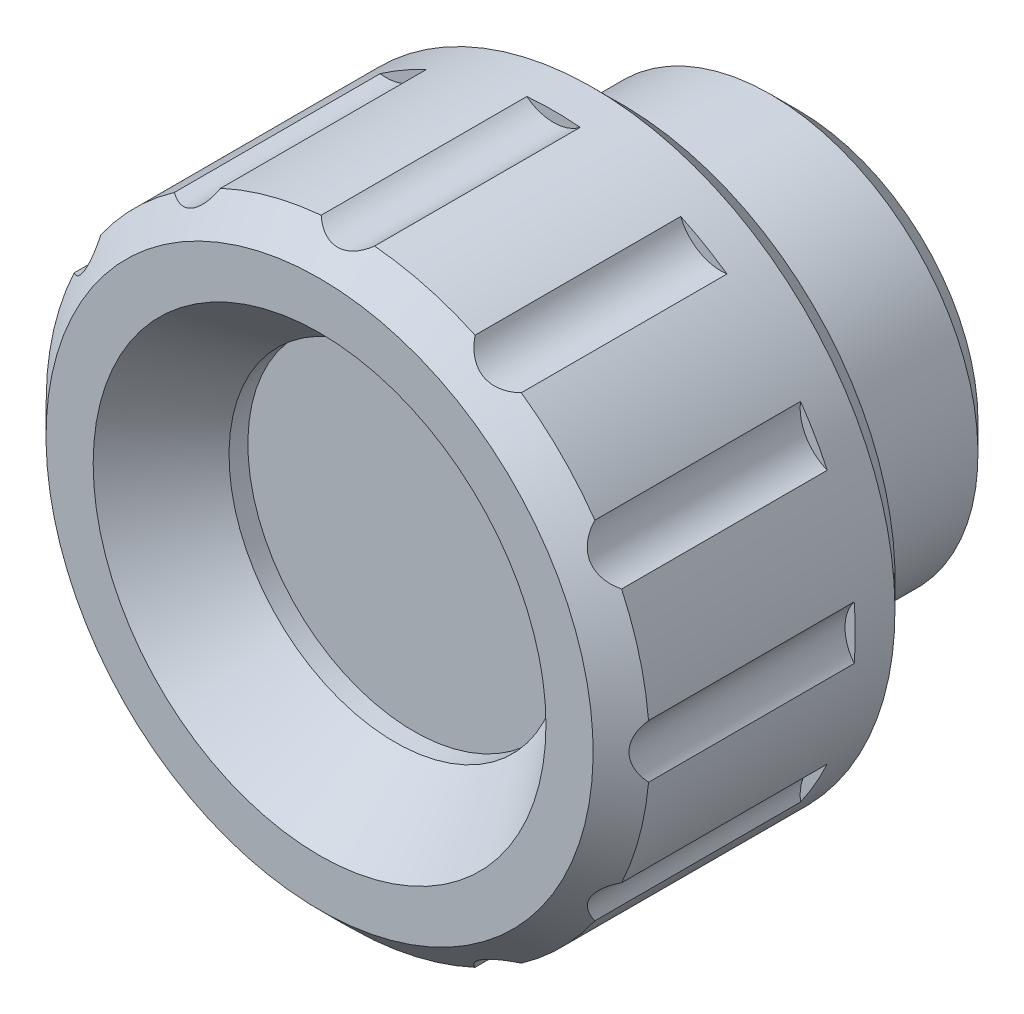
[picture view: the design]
ISO-10303-21;
HEADER;
FILE_DESCRIPTION(('STEP AP214'),'2;1');
FILE_NAME('part.step','',(''),(''),'','','');
FILE_SCHEMA(('AUTOMOTIVE_DESIGN { 1 0 10303 214 1 1 1 1 }'));
ENDSEC;
DATA;
#1=APPLICATION_CONTEXT('core data for automotive mechanical design processes');
#2=APPLICATION_PROTOCOL_DEFINITION('international standard','automotive_design',2000,#1);
#3=PRODUCT_CONTEXT('',#1,'mechanical');
#4=PRODUCT('Part','Part','',(#3));
#5=PRODUCT_RELATED_PRODUCT_CATEGORY('part','',(#4));
#6=PRODUCT_DEFINITION_FORMATION('','',#4);
#7=PRODUCT_DEFINITION_CONTEXT('part definition',#1,'design');
#8=PRODUCT_DEFINITION('design','',#6,#7);
#9=PRODUCT_DEFINITION_SHAPE('','',#8);
#10=(LENGTH_UNIT() NAMED_UNIT(*) SI_UNIT(.MILLI.,.METRE.));
#11=(NAMED_UNIT(*) PLANE_ANGLE_UNIT() SI_UNIT($,.RADIAN.));
#12=(NAMED_UNIT(*) SI_UNIT($,.STERADIAN.) SOLID_ANGLE_UNIT());
#13=UNCERTAINTY_MEASURE_WITH_UNIT(LENGTH_MEASURE(1.E-05),#10,'distance_accuracy_value','');
#14=(GEOMETRIC_REPRESENTATION_CONTEXT(3) GLOBAL_UNCERTAINTY_ASSIGNED_CONTEXT((#13)) GLOBAL_UNIT_ASSIGNED_CONTEXT((#10,
#11,#12)) REPRESENTATION_CONTEXT('',''));
#15=CARTESIAN_POINT('',(0.,0.,0.));
#16=DIRECTION('',(0.,0.,1.));
#17=DIRECTION('',(1.,0.,0.));
#18=AXIS2_PLACEMENT_3D('',#15,#16,#17);
#19=CARTESIAN_POINT('',(3.49999999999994,0.,0.));
#20=DIRECTION('',(0.,0.,-1.));
#21=DIRECTION('',(0.,1.,0.));
#22=AXIS2_PLACEMENT_3D('',#19,#20,#21);
#23=PLANE('',#22);
#24=CARTESIAN_POINT('',(0.,0.,0.));
#25=DIRECTION('',(0.,0.,-1.));
#26=DIRECTION('',(-1.,0.,0.));
#27=AXIS2_PLACEMENT_3D('',#24,#25,#26);
#28=CIRCLE('',#27,2.4);
#29=CARTESIAN_POINT('',(-2.4,0.,0.));
#30=VERTEX_POINT('',#29);
#31=EDGE_CURVE('E9',#30,#30,#28,.F.);
#32=ORIENTED_EDGE('',*,*,#31,.T.);
#33=EDGE_LOOP('',(#32));
#34=FACE_BOUND('',#33,.T.);
#35=CARTESIAN_POINT('',(0.,0.,0.));
#36=DIRECTION('',(0.,0.,-1.));
#37=DIRECTION('',(0.,1.,0.));
#38=AXIS2_PLACEMENT_3D('',#35,#36,#37);
#39=CIRCLE('',#38,3.49999999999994);
#40=CARTESIAN_POINT('',(0.,3.49999999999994,0.));
#41=VERTEX_POINT('',#40);
#42=EDGE_CURVE('E354',#41,#41,#39,.T.);
#43=ORIENTED_EDGE('',*,*,#42,.T.);
#44=EDGE_LOOP('',(#43));
#45=FACE_BOUND('',#44,.T.);
#46=ADVANCED_FACE('F14',(#34,#45),#23,.T.);
#47=CARTESIAN_POINT('',(0.,0.,0.));
#48=DIRECTION('',(0.,0.,-1.));
#49=DIRECTION('',(0.,1.,0.));
#50=AXIS2_PLACEMENT_3D('',#47,#48,#49);
#51=CYLINDRICAL_SURFACE('',#50,3.49999999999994);
#52=CARTESIAN_POINT('',(0.,0.,0.300000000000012));
#53=DIRECTION('',(0.,0.,-1.));
#54=DIRECTION('',(0.,1.,0.));
#55=AXIS2_PLACEMENT_3D('',#52,#53,#54);
#56=CIRCLE('',#55,3.49999999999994);
#57=CARTESIAN_POINT('',(0.,3.49999999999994,0.300000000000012));
#58=VERTEX_POINT('',#57);
#59=EDGE_CURVE('E351',#58,#58,#56,.T.);
#60=ORIENTED_EDGE('',*,*,#59,.T.);
#61=EDGE_LOOP('',(#60));
#62=FACE_BOUND('',#61,.T.);
#63=ORIENTED_EDGE('',*,*,#42,.F.);
#64=EDGE_LOOP('',(#63));
#65=FACE_BOUND('',#64,.T.);
#66=ADVANCED_FACE('F406',(#62,#65),#51,.T.);
#67=CARTESIAN_POINT('',(4.74999999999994,0.,0.300000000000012));
#68=DIRECTION('',(0.,0.,-1.));
#69=DIRECTION('',(0.,1.,0.));
#70=AXIS2_PLACEMENT_3D('',#67,#68,#69);
#71=PLANE('',#70);
#72=CARTESIAN_POINT('',(0.,0.,0.300000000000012));
#73=DIRECTION('',(0.,0.,-1.));
#74=DIRECTION('',(0.,1.,0.));
#75=AXIS2_PLACEMENT_3D('',#72,#73,#74);
#76=CIRCLE('',#75,4.74999999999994);
#77=CARTESIAN_POINT('',(0.,4.74999999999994,0.300000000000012));
#78=VERTEX_POINT('',#77);
#79=EDGE_CURVE('E348',#78,#78,#76,.T.);
#80=ORIENTED_EDGE('',*,*,#79,.T.);
#81=EDGE_LOOP('',(#80));
#82=FACE_BOUND('',#81,.T.);
#83=ORIENTED_EDGE('',*,*,#59,.F.);
#84=EDGE_LOOP('',(#83));
#85=FACE_BOUND('',#84,.T.);
#86=ADVANCED_FACE('F413',(#82,#85),#71,.T.);
#87=CARTESIAN_POINT('',(0.,0.,0.300000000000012));
#88=DIRECTION('',(0.,0.,1.));
#89=DIRECTION('',(0.,-1.,0.));
#90=AXIS2_PLACEMENT_3D('',#87,#88,#89);
#91=CONICAL_SURFACE('',#90,4.74999999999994,0.785398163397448);
#92=CARTESIAN_POINT('',(0.,0.,1.05000000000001));
#93=DIRECTION('',(0.,0.,-1.));
#94=DIRECTION('',(0.,1.,0.));
#95=AXIS2_PLACEMENT_3D('',#92,#93,#94);
#96=CIRCLE('',#95,5.49999999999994);
#97=CARTESIAN_POINT('',(0.,5.49999999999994,1.05000000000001));
#98=VERTEX_POINT('',#97);
#99=EDGE_CURVE('E344',#98,#98,#96,.T.);
#100=ORIENTED_EDGE('',*,*,#99,.T.);
#101=EDGE_LOOP('',(#100));
#102=FACE_BOUND('',#101,.T.);
#103=ORIENTED_EDGE('',*,*,#79,.F.);
#104=EDGE_LOOP('',(#103));
#105=FACE_BOUND('',#104,.T.);
#106=ADVANCED_FACE('F864',(#102,#105),#91,.T.);
#107=CARTESIAN_POINT('',(0.,0.,0.));
#108=DIRECTION('',(0.,0.,-1.));
#109=DIRECTION('',(0.,1.,0.));
#110=AXIS2_PLACEMENT_3D('',#107,#108,#109);
#111=CYLINDRICAL_SURFACE('',#110,5.49999999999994);
#112=CARTESIAN_POINT('',(0.,0.,5.));
#113=DIRECTION('',(0.,0.,-1.));
#114=DIRECTION('',(-1.,0.,0.));
#115=AXIS2_PLACEMENT_3D('',#112,#113,#114);
#116=CIRCLE('',#115,5.49999999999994);
#117=CARTESIAN_POINT('',(-5.49999999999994,0.,5.));
#118=VERTEX_POINT('',#117);
#119=EDGE_CURVE('E211',#118,#118,#116,.F.);
#120=ORIENTED_EDGE('',*,*,#119,.F.);
#121=EDGE_LOOP('',(#120));
#122=FACE_BOUND('',#121,.T.);
#123=ORIENTED_EDGE('',*,*,#99,.F.);
#124=EDGE_LOOP('',(#123));
#125=FACE_BOUND('',#124,.T.);
#126=ADVANCED_FACE('F465',(#122,#125),#111,.T.);
#127=CARTESIAN_POINT('',(0.,8.,5.));
#128=DIRECTION('',(0.,0.,-1.));
#129=DIRECTION('',(-1.,0.,0.));
#130=AXIS2_PLACEMENT_3D('',#127,#128,#129);
#131=PLANE('',#130);
#132=CARTESIAN_POINT('',(0.,0.,5.));
#133=DIRECTION('',(0.,0.,-1.));
#134=DIRECTION('',(-1.,0.,0.));
#135=AXIS2_PLACEMENT_3D('',#132,#133,#134);
#136=CIRCLE('',#135,7.25);
#137=CARTESIAN_POINT('',(-7.25,0.,5.));
#138=VERTEX_POINT('',#137);
#139=EDGE_CURVE('E216',#138,#138,#136,.T.);
#140=ORIENTED_EDGE('',*,*,#139,.T.);
#141=EDGE_LOOP('',(#140));
#142=FACE_BOUND('',#141,.T.);
#143=ORIENTED_EDGE('',*,*,#119,.T.);
#144=EDGE_LOOP('',(#143));
#145=FACE_BOUND('',#144,.T.);
#146=ADVANCED_FACE('F420',(#142,#145),#131,.T.);
#147=CARTESIAN_POINT('',(4.4,0.,10.5000000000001));
#148=DIRECTION('',(0.,0.,1.));
#149=DIRECTION('',(0.,-1.,0.));
#150=AXIS2_PLACEMENT_3D('',#147,#148,#149);
#151=PLANE('',#150);
#152=CARTESIAN_POINT('',(0.,0.,10.5000000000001));
#153=DIRECTION('',(0.,0.,-1.));
#154=DIRECTION('',(0.,1.,0.));
#155=AXIS2_PLACEMENT_3D('',#152,#153,#154);
#156=CIRCLE('',#155,4.4);
#157=CARTESIAN_POINT('',(0.,4.4,10.5000000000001));
#158=VERTEX_POINT('',#157);
#159=EDGE_CURVE('E288',#158,#158,#156,.T.);
#160=ORIENTED_EDGE('',*,*,#159,.F.);
#161=EDGE_LOOP('',(#160));
#162=FACE_BOUND('',#161,.T.);
#163=ADVANCED_FACE('F394',(#162),#151,.T.);
#164=CARTESIAN_POINT('',(0.,0.,0.));
#165=DIRECTION('',(0.,0.,-1.));
#166=DIRECTION('',(0.,1.,0.));
#167=AXIS2_PLACEMENT_3D('',#164,#165,#166);
#168=CYLINDRICAL_SURFACE('',#167,4.4);
#169=ORIENTED_EDGE('',*,*,#159,.T.);
#170=EDGE_LOOP('',(#169));
#171=FACE_BOUND('',#170,.T.);
#172=CARTESIAN_POINT('',(0.,0.,11.));
#173=DIRECTION('',(0.,0.,-1.));
#174=DIRECTION('',(0.,1.,0.));
#175=AXIS2_PLACEMENT_3D('',#172,#173,#174);
#176=CIRCLE('',#175,4.4);
#177=CARTESIAN_POINT('',(0.,4.4,11.));
#178=VERTEX_POINT('',#177);
#179=EDGE_CURVE('E332',#178,#178,#176,.T.);
#180=ORIENTED_EDGE('',*,*,#179,.F.);
#181=EDGE_LOOP('',(#180));
#182=FACE_BOUND('',#181,.T.);
#183=ADVANCED_FACE('F390',(#171,#182),#168,.F.);
#184=CARTESIAN_POINT('',(0.,0.,13.));
#185=DIRECTION('',(0.,0.,1.));
#186=DIRECTION('',(0.,-1.,0.));
#187=AXIS2_PLACEMENT_3D('',#184,#185,#186);
#188=CONICAL_SURFACE('',#187,6.,0.67474094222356);
#189=ORIENTED_EDGE('',*,*,#179,.T.);
#190=EDGE_LOOP('',(#189));
#191=FACE_BOUND('',#190,.T.);
#192=CARTESIAN_POINT('',(0.,0.,13.));
#193=DIRECTION('',(0.,0.,-1.));
#194=DIRECTION('',(0.,1.,0.));
#195=AXIS2_PLACEMENT_3D('',#192,#193,#194);
#196=CIRCLE('',#195,6.);
#197=CARTESIAN_POINT('',(0.,6.,13.));
#198=VERTEX_POINT('',#197);
#199=EDGE_CURVE('E335',#198,#198,#196,.T.);
#200=ORIENTED_EDGE('',*,*,#199,.F.);
#201=EDGE_LOOP('',(#200));
#202=FACE_BOUND('',#201,.T.);
#203=ADVANCED_FACE('F393',(#191,#202),#188,.F.);
#204=CARTESIAN_POINT('',(6.,0.,13.));
#205=DIRECTION('',(0.,0.,1.));
#206=DIRECTION('',(0.,-1.,0.));
#207=AXIS2_PLACEMENT_3D('',#204,#205,#206);
#208=PLANE('',#207);
#209=ORIENTED_EDGE('',*,*,#199,.T.);
#210=EDGE_LOOP('',(#209));
#211=FACE_BOUND('',#210,.T.);
#212=CARTESIAN_POINT('',(0.,0.,13.));
#213=DIRECTION('',(0.,0.,-1.));
#214=DIRECTION('',(0.,1.,0.));
#215=AXIS2_PLACEMENT_3D('',#212,#213,#214);
#216=CIRCLE('',#215,7.25);
#217=CARTESIAN_POINT('',(0.,7.25,13.));
#218=VERTEX_POINT('',#217);
#219=EDGE_CURVE('E338',#218,#218,#216,.T.);
#220=ORIENTED_EDGE('',*,*,#219,.F.);
#221=EDGE_LOOP('',(#220));
#222=FACE_BOUND('',#221,.T.);
#223=ADVANCED_FACE('F386',(#211,#222),#208,.T.);
#224=CARTESIAN_POINT('',(0.,0.,6.8));
#225=DIRECTION('',(0.,0.,1.));
#226=DIRECTION('',(0.,-1.,0.));
#227=AXIS2_PLACEMENT_3D('',#224,#225,#226);
#228=PLANE('',#227);
#229=CARTESIAN_POINT('',(-1.2490009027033E-13,-8.87500000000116,6.8));
#230=DIRECTION('',(0.,0.,-1.));
#231=DIRECTION('',(0.,-1.,0.));
#232=AXIS2_PLACEMENT_3D('',#229,#230,#231);
#233=CIRCLE('',#232,1.15);
#234=CARTESIAN_POINT('',(-0.707804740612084,-7.96862676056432,6.8));
#235=VERTEX_POINT('',#234);
#236=CARTESIAN_POINT('',(0.70780474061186,-7.96862676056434,6.8));
#237=VERTEX_POINT('',#236);
#238=EDGE_CURVE('E275',#235,#237,#233,.T.);
#239=ORIENTED_EDGE('',*,*,#238,.F.);
#240=CARTESIAN_POINT('',(0.,0.,6.8));
#241=DIRECTION('',(0.,0.,1.));
#242=DIRECTION('',(0.,-1.,0.));
#243=AXIS2_PLACEMENT_3D('',#240,#241,#242);
#244=CIRCLE('',#243,8.);
#245=EDGE_CURVE('E222',#237,#235,#244,.F.);
#246=ORIENTED_EDGE('',*,*,#245,.F.);
#247=EDGE_LOOP('',(#239,#246));
#248=FACE_BOUND('',#247,.T.);
#249=ADVANCED_FACE('F382',(#248),#228,.T.);
#250=CARTESIAN_POINT('',(-1.2490009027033E-13,-8.87500000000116,6.8));
#251=DIRECTION('',(0.,0.,1.));
#252=DIRECTION('',(0.,-1.,0.));
#253=AXIS2_PLACEMENT_3D('',#250,#251,#252);
#254=CYLINDRICAL_SURFACE('',#253,1.15);
#255=DIRECTION('',(0.,0.,1.));
#256=VECTOR('',#255,1.);
#257=CARTESIAN_POINT('',(-0.707804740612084,-7.96862676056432,6.8));
#258=LINE('',#257,#256);
#259=CARTESIAN_POINT('',(-0.707804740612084,-7.96862676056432,12.2499999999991));
#260=VERTEX_POINT('',#259);
#261=EDGE_CURVE('E301',#235,#260,#258,.T.);
#262=ORIENTED_EDGE('',*,*,#261,.F.);
#263=ORIENTED_EDGE('',*,*,#238,.T.);
#264=DIRECTION('',(0.,0.,1.));
#265=VECTOR('',#264,1.);
#266=CARTESIAN_POINT('',(0.70780474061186,-7.96862676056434,6.8));
#267=LINE('',#266,#265);
#268=CARTESIAN_POINT('',(0.707804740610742,-7.96862676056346,12.25));
#269=VERTEX_POINT('',#268);
#270=EDGE_CURVE('E299',#237,#269,#267,.T.);
#271=ORIENTED_EDGE('',*,*,#270,.T.);
#272=CARTESIAN_POINT('',(-0.708004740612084,-7.96878298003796,12.2498266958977));
#273=CARTESIAN_POINT('',(-0.670016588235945,-7.93910304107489,12.2827435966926));
#274=CARTESIAN_POINT('',(-0.629096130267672,-7.91098728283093,12.3141461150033));
#275=CARTESIAN_POINT('',(-0.541113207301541,-7.85895957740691,12.3725489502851));
#276=CARTESIAN_POINT('',(-0.493993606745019,-7.83509230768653,12.3995022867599));
#277=CARTESIAN_POINT('',(-0.403110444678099,-7.79705455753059,12.4426329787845));
#278=CARTESIAN_POINT('',(-0.360275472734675,-7.7819114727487,12.4598771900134));
#279=CARTESIAN_POINT('',(-0.271519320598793,-7.75656520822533,12.4888070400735));
#280=CARTESIAN_POINT('',(-0.225610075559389,-7.74634405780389,12.5005128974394));
#281=CARTESIAN_POINT('',(-0.131281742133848,-7.73151414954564,12.5175147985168));
#282=CARTESIAN_POINT('',(-0.0828445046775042,-7.72695427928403,12.522755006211));
#283=CARTESIAN_POINT('',(0.014487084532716,-7.72406175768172,12.5260777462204));
#284=CARTESIAN_POINT('',(0.0633815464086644,-7.72573064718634,12.5241585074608));
#285=CARTESIAN_POINT('',(0.154026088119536,-7.73456075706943,12.5140225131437));
#286=CARTESIAN_POINT('',(0.195934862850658,-7.74104594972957,12.5065809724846));
#287=CARTESIAN_POINT('',(0.277692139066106,-7.7582480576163,12.4868901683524));
#288=CARTESIAN_POINT('',(0.31753961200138,-7.76896706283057,12.4746385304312));
#289=CARTESIAN_POINT('',(0.408286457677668,-7.79851491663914,12.440973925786));
#290=CARTESIAN_POINT('',(0.458050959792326,-7.8188729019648,12.4178517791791));
#291=CARTESIAN_POINT('',(0.551931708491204,-7.86474498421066,12.3660439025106));
#292=CARTESIAN_POINT('',(0.596041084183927,-7.89026525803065,12.3373515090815));
#293=CARTESIAN_POINT('',(0.661880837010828,-7.93410696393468,12.2883657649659));
#294=CARTESIAN_POINT('',(0.685443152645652,-7.95116148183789,12.2693731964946));
#295=CARTESIAN_POINT('',(0.708004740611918,-7.96878298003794,12.2498266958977));
#296=B_SPLINE_CURVE_WITH_KNOTS('',3,(#272,#273,#274,#275,#276,#277,#278,#279,#280,#281,#282,
#283,#284,#285,#286,#287,#288,#289,#290,#291,#292,#293,#294,#295),.UNSPECIFIED.,.F.,.F.,(4,2,2,
2,2,2,2,2,2,2,2,4),(0.,0.17542065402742,0.352589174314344,0.497789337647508,0.642455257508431,
0.78836193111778,0.934304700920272,1.06290984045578,1.19157854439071,1.36619586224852,
1.54102336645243,1.64509140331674),.UNSPECIFIED.);
#297=EDGE_CURVE('E493',#260,#269,#296,.T.);
#298=ORIENTED_EDGE('',*,*,#297,.F.);
#299=EDGE_LOOP('',(#262,#263,#271,#298));
#300=FACE_BOUND('',#299,.T.);
#301=ADVANCED_FACE('F385',(#300),#254,.F.);
#302=CARTESIAN_POINT('',(4.43750000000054,-7.68597545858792,6.8));
#303=DIRECTION('',(0.,0.,-1.));
#304=DIRECTION('',(0.,-1.,0.));
#305=AXIS2_PLACEMENT_3D('',#302,#303,#304);
#306=CIRCLE('',#305,1.15);
#307=CARTESIAN_POINT('',(3.37133649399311,-7.25493557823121,6.8));
#308=VERTEX_POINT('',#307);
#309=CARTESIAN_POINT('',(4.59729026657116,-6.54713083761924,6.8));
#310=VERTEX_POINT('',#309);
#311=EDGE_CURVE('E278',#308,#310,#306,.T.);
#312=ORIENTED_EDGE('',*,*,#311,.F.);
#313=EDGE_CURVE('E218',#310,#308,#244,.F.);
#314=ORIENTED_EDGE('',*,*,#313,.F.);
#315=EDGE_LOOP('',(#312,#314));
#316=FACE_BOUND('',#315,.T.);
#317=ADVANCED_FACE('F389',(#316),#228,.T.);
#318=CARTESIAN_POINT('',(4.43750000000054,-7.68597545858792,6.8));
#319=DIRECTION('',(0.,0.,1.));
#320=DIRECTION('',(0.,-1.,0.));
#321=AXIS2_PLACEMENT_3D('',#318,#319,#320);
#322=CYLINDRICAL_SURFACE('',#321,1.15);
#323=DIRECTION('',(0.,0.,1.));
#324=VECTOR('',#323,1.);
#325=CARTESIAN_POINT('',(3.37133649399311,-7.25493557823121,6.8));
#326=LINE('',#325,#324);
#327=CARTESIAN_POINT('',(3.37133649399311,-7.25493557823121,12.2499999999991));
#328=VERTEX_POINT('',#327);
#329=EDGE_CURVE('E297',#308,#328,#326,.T.);
#330=ORIENTED_EDGE('',*,*,#329,.F.);
#331=ORIENTED_EDGE('',*,*,#311,.T.);
#332=DIRECTION('',(0.,0.,1.));
#333=VECTOR('',#332,1.);
#334=CARTESIAN_POINT('',(4.59729026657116,-6.54713083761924,6.8));
#335=LINE('',#334,#333);
#336=CARTESIAN_POINT('',(4.59729026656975,-6.54713083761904,12.25));
#337=VERTEX_POINT('',#336);
#338=EDGE_CURVE('E295',#310,#337,#335,.T.);
#339=ORIENTED_EDGE('',*,*,#338,.T.);
#340=CARTESIAN_POINT('',(3.37125565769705,-7.25513557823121,12.2498526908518));
#341=CARTESIAN_POINT('',(3.38931533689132,-7.2104398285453,12.2827673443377));
#342=CARTESIAN_POINT('',(3.41069638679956,-7.16563264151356,12.3141675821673));
#343=CARTESIAN_POINT('',(3.46087905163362,-7.07658806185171,12.3725658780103));
#344=CARTESIAN_POINT('',(3.48975247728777,-7.032360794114,12.399516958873));
#345=CARTESIAN_POINT('',(3.54944136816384,-6.95398075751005,12.4426442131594));
#346=CARTESIAN_POINT('',(3.57896658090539,-6.91945000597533,12.459887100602));
#347=CARTESIAN_POINT('',(3.64315945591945,-6.85312362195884,12.4888142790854));
#348=CARTESIAN_POINT('',(3.67780779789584,-6.82131839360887,12.5005187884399));
#349=CARTESIAN_POINT('',(3.75208390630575,-6.76131362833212,12.5175180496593));
#350=CARTESIAN_POINT('',(3.79175182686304,-6.73314735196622,12.5227569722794));
#351=CARTESIAN_POINT('',(3.87459677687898,-6.68197914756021,12.5260773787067));
#352=CARTESIAN_POINT('',(3.91777467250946,-6.65897849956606,12.5241570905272));
#353=CARTESIAN_POINT('',(4.00068974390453,-6.62130533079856,12.5140193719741));
#354=CARTESIAN_POINT('',(4.04022639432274,-6.60596809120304,12.5065770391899));
#355=CARTESIAN_POINT('',(4.1196311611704,-6.57998847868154,12.4868847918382));
#356=CARTESIAN_POINT('',(4.15949943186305,-6.56934843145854,12.4746325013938));
#357=CARTESIAN_POINT('',(4.25286326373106,-6.54956561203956,12.4409660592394));
#358=CARTESIAN_POINT('',(4.30614049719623,-6.54231471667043,12.4178426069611));
#359=CARTESIAN_POINT('',(4.41038121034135,-6.53510255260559,12.3660321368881));
#360=CARTESIAN_POINT('',(4.46134183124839,-6.53515005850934,12.3373384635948));
#361=CARTESIAN_POINT('',(4.54025639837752,-6.54019818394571,12.2883669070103));
#362=CARTESIAN_POINT('',(4.56916440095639,-6.54318368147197,12.269391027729));
#363=CARTESIAN_POINT('',(4.59749026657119,-6.5471589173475,12.2498620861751));
#364=B_SPLINE_CURVE_WITH_KNOTS('',3,(#340,#341,#342,#343,#344,#345,#346,#347,#348,#349,#350,
#351,#352,#353,#354,#355,#356,#357,#358,#359,#360,#361,#362,#363),.UNSPECIFIED.,.F.,.F.,(4,2,2,
2,2,2,2,2,2,2,2,4),(0.,0.175413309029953,0.352574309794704,0.497771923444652,0.64243531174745,
0.788339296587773,0.934279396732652,1.06288407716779,1.19155236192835,1.36617341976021,
1.54100441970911,1.64498267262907),.UNSPECIFIED.);
#365=EDGE_CURVE('E486',#328,#337,#364,.T.);
#366=ORIENTED_EDGE('',*,*,#365,.F.);
#367=EDGE_LOOP('',(#330,#331,#339,#366));
#368=FACE_BOUND('',#367,.T.);
#369=ADVANCED_FACE('F500',(#368),#322,.F.);
#370=CARTESIAN_POINT('',(7.68597545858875,-4.43749999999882,6.8));
#371=DIRECTION('',(0.,0.,-1.));
#372=DIRECTION('',(0.,-1.,0.));
#373=AXIS2_PLACEMENT_3D('',#370,#371,#372);
#374=CIRCLE('',#373,1.15000000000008);
#375=CARTESIAN_POINT('',(6.54713083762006,-4.59729026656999,6.8));
#376=VERTEX_POINT('',#375);
#377=CARTESIAN_POINT('',(7.25493557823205,-3.37133649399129,6.8));
#378=VERTEX_POINT('',#377);
#379=EDGE_CURVE('E281',#376,#378,#374,.T.);
#380=ORIENTED_EDGE('',*,*,#379,.F.);
#381=EDGE_CURVE('E212',#378,#376,#244,.F.);
#382=ORIENTED_EDGE('',*,*,#381,.F.);
#383=EDGE_LOOP('',(#380,#382));
#384=FACE_BOUND('',#383,.T.);
#385=ADVANCED_FACE('F503',(#384),#228,.T.);
#386=CARTESIAN_POINT('',(7.68597545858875,-4.43749999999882,6.8));
#387=DIRECTION('',(0.,0.,1.));
#388=DIRECTION('',(0.,-1.,0.));
#389=AXIS2_PLACEMENT_3D('',#386,#387,#388);
#390=CYLINDRICAL_SURFACE('',#389,1.15000000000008);
#391=DIRECTION('',(0.,0.,1.));
#392=VECTOR('',#391,1.);
#393=CARTESIAN_POINT('',(6.54713083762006,-4.59729026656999,6.8));
#394=LINE('',#393,#392);
#395=CARTESIAN_POINT('',(6.54713083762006,-4.59729026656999,12.2499999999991));
#396=VERTEX_POINT('',#395);
#397=EDGE_CURVE('E293',#376,#396,#394,.T.);
#398=ORIENTED_EDGE('',*,*,#397,.F.);
#399=ORIENTED_EDGE('',*,*,#379,.T.);
#400=DIRECTION('',(0.,0.,1.));
#401=VECTOR('',#400,1.);
#402=CARTESIAN_POINT('',(7.25493557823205,-3.37133649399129,6.8));
#403=LINE('',#402,#401);
#404=CARTESIAN_POINT('',(7.25493557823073,-3.37133649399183,12.25));
#405=VERTEX_POINT('',#404);
#406=EDGE_CURVE('E291',#378,#405,#403,.T.);
#407=ORIENTED_EDGE('',*,*,#406,.T.);
#408=CARTESIAN_POINT('',(6.54715891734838,-4.59749026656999,12.249862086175));
#409=CARTESIAN_POINT('',(6.54045182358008,-4.54975319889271,12.2827759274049));
#410=CARTESIAN_POINT('',(6.53656536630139,-4.50025899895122,12.3141753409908));
#411=CARTESIAN_POINT('',(6.53550363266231,-4.39805391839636,12.3725719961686));
#412=CARTESIAN_POINT('',(6.53839560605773,-4.34531590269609,12.3995222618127));
#413=CARTESIAN_POINT('',(6.55089846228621,-4.24759324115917,12.4426482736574));
#414=CARTESIAN_POINT('',(6.55920303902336,-4.20292634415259,12.4598906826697));
#415=CARTESIAN_POINT('',(6.58163319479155,-4.11339009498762,12.4888168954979));
#416=CARTESIAN_POINT('',(6.59573724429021,-4.06852209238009,12.5005209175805));
#417=CARTESIAN_POINT('',(6.63006040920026,-3.97941910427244,12.5175192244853));
#418=CARTESIAN_POINT('',(6.65033092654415,-3.93519284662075,12.5227576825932));
#419=CARTESIAN_POINT('',(6.69649299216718,-3.84945829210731,12.5260772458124));
#420=CARTESIAN_POINT('',(6.72238593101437,-3.8079506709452,12.5241565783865));
#421=CARTESIAN_POINT('',(6.77535612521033,-3.73386792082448,12.5140182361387));
#422=CARTESIAN_POINT('',(6.80192739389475,-3.70081740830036,12.5065756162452));
#423=CARTESIAN_POINT('',(6.85770436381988,-3.63861654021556,12.486882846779));
#424=CARTESIAN_POINT('',(6.88691136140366,-3.60946812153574,12.4746303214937));
#425=CARTESIAN_POINT('',(6.95787590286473,-3.54565408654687,12.4409632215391));
#426=CARTESIAN_POINT('',(7.00039031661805,-3.51273611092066,12.4178393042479));
#427=CARTESIAN_POINT('',(7.08706015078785,-3.45437012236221,12.3660279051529));
#428=CARTESIAN_POINT('',(7.13121748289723,-3.42893113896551,12.3373337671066));
#429=CARTESIAN_POINT('',(7.20208570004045,-3.39384524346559,12.2883604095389));
#430=CARTESIAN_POINT('',(7.22861528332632,-3.38197627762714,12.2693831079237));
#431=CARTESIAN_POINT('',(7.25513557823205,-3.37125565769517,12.2498526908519));
#432=B_SPLINE_CURVE_WITH_KNOTS('',3,(#408,#409,#410,#411,#412,#413,#414,#415,#416,#417,#418,
#419,#420,#421,#422,#423,#424,#425,#426,#427,#428,#429,#430,#431),.UNSPECIFIED.,.F.,.F.,(4,2,2,
2,2,2,2,2,2,2,2,4),(0.,0.175410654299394,0.352568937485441,0.497765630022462,0.642428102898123,
0.788331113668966,0.934270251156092,1.06287477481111,1.19154289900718,1.36616525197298,
1.54099757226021,1.64498268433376),.UNSPECIFIED.);
#433=EDGE_CURVE('E207',#396,#405,#432,.T.);
#434=ORIENTED_EDGE('',*,*,#433,.F.);
#435=EDGE_LOOP('',(#398,#399,#407,#434));
#436=FACE_BOUND('',#435,.T.);
#437=ADVANCED_FACE('F472',(#436),#390,.F.);
#438=CARTESIAN_POINT('',(8.87500000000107,1.83793952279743E-12,6.8));
#439=DIRECTION('',(0.,0.,-1.));
#440=DIRECTION('',(0.,-1.,0.));
#441=AXIS2_PLACEMENT_3D('',#438,#439,#440);
#442=CIRCLE('',#441,1.15);
#443=CARTESIAN_POINT('',(7.96862676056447,-0.707804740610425,6.8));
#444=VERTEX_POINT('',#443);
#445=CARTESIAN_POINT('',(7.96862676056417,0.707804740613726,6.8));
#446=VERTEX_POINT('',#445);
#447=EDGE_CURVE('E189',#444,#446,#442,.T.);
#448=ORIENTED_EDGE('',*,*,#447,.F.);
#449=EDGE_CURVE('E203',#446,#444,#244,.F.);
#450=ORIENTED_EDGE('',*,*,#449,.F.);
#451=EDGE_LOOP('',(#448,#450));
#452=FACE_BOUND('',#451,.T.);
#453=ADVANCED_FACE('F470',(#452),#228,.T.);
#454=CARTESIAN_POINT('',(8.87500000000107,1.83793952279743E-12,6.8));
#455=DIRECTION('',(0.,0.,1.));
#456=DIRECTION('',(0.,-1.,0.));
#457=AXIS2_PLACEMENT_3D('',#454,#455,#456);
#458=CYLINDRICAL_SURFACE('',#457,1.15);
#459=DIRECTION('',(0.,0.,1.));
#460=VECTOR('',#459,1.);
#461=CARTESIAN_POINT('',(7.96862676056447,-0.707804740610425,6.8));
#462=LINE('',#461,#460);
#463=CARTESIAN_POINT('',(7.96862676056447,-0.707804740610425,12.2499999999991));
#464=VERTEX_POINT('',#463);
#465=EDGE_CURVE('E289',#444,#464,#462,.T.);
#466=ORIENTED_EDGE('',*,*,#465,.F.);
#467=ORIENTED_EDGE('',*,*,#447,.T.);
#468=DIRECTION('',(0.,0.,1.));
#469=VECTOR('',#468,1.);
#470=CARTESIAN_POINT('',(7.96862676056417,0.707804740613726,6.8));
#471=LINE('',#470,#469);
#472=CARTESIAN_POINT('',(7.9686267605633,0.707804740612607,12.25));
#473=VERTEX_POINT('',#472);
#474=EDGE_CURVE('E286',#446,#473,#471,.T.);
#475=ORIENTED_EDGE('',*,*,#474,.T.);
#476=CARTESIAN_POINT('',(7.9687829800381,-0.708004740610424,12.2498266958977));
#477=CARTESIAN_POINT('',(7.93910304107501,-0.670016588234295,12.2827435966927));
#478=CARTESIAN_POINT('',(7.91098728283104,-0.629096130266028,12.3141461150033));
#479=CARTESIAN_POINT('',(7.85895957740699,-0.541113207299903,12.3725489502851));
#480=CARTESIAN_POINT('',(7.83509230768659,-0.49399360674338,12.3995022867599));
#481=CARTESIAN_POINT('',(7.79705455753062,-0.403110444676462,12.4426329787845));
#482=CARTESIAN_POINT('',(7.78191147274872,-0.36027547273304,12.4598771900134));
#483=CARTESIAN_POINT('',(7.75656520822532,-0.271519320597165,12.4888070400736));
#484=CARTESIAN_POINT('',(7.74634405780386,-0.225610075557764,12.5005128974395));
#485=CARTESIAN_POINT('',(7.73151414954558,-0.131281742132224,12.5175147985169));
#486=CARTESIAN_POINT('',(7.72695427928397,-0.0828445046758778,12.5227550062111));
#487=CARTESIAN_POINT('',(7.72406175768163,0.0144870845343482,12.5260777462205));
#488=CARTESIAN_POINT('',(7.72573064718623,0.0633815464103,12.5241585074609));
#489=CARTESIAN_POINT('',(7.7345607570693,0.154026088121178,12.5140225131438));
#490=CARTESIAN_POINT('',(7.74104594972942,0.195934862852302,12.5065809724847));
#491=CARTESIAN_POINT('',(7.75824805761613,0.277692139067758,12.4868901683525));
#492=CARTESIAN_POINT('',(7.76896706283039,0.317539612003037,12.4746385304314));
#493=CARTESIAN_POINT('',(7.79851491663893,0.408286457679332,12.4409739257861));
#494=CARTESIAN_POINT('',(7.81887290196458,0.458050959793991,12.4178517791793));
#495=CARTESIAN_POINT('',(7.86474498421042,0.551931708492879,12.3660439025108));
#496=CARTESIAN_POINT('',(7.89026525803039,0.596041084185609,12.3373515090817));
#497=CARTESIAN_POINT('',(7.93410696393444,0.661880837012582,12.288365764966));
#498=CARTESIAN_POINT('',(7.95116148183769,0.685443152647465,12.2693731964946));
#499=CARTESIAN_POINT('',(7.96878298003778,0.708004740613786,12.2498266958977));
#500=B_SPLINE_CURVE_WITH_KNOTS('',3,(#476,#477,#478,#479,#480,#481,#482,#483,#484,#485,#486,
#487,#488,#489,#490,#491,#492,#493,#494,#495,#496,#497,#498,#499),.UNSPECIFIED.,.F.,.F.,(4,2,2,
2,2,2,2,2,2,2,2,4),(0.,0.175420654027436,0.352589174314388,0.497789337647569,0.642455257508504,
0.788361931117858,0.934304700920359,1.06290984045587,1.19157854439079,1.36619586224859,
1.5410233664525,1.64509140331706),.UNSPECIFIED.);
#501=EDGE_CURVE('E201',#464,#473,#500,.T.);
#502=ORIENTED_EDGE('',*,*,#501,.F.);
#503=EDGE_LOOP('',(#466,#467,#475,#502));
#504=FACE_BOUND('',#503,.T.);
#505=ADVANCED_FACE('F466',(#504),#458,.F.);
#506=CARTESIAN_POINT('',(7.68597545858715,4.43750000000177,6.8));
#507=DIRECTION('',(0.,0.,-1.));
#508=DIRECTION('',(0.,-1.,0.));
#509=AXIS2_PLACEMENT_3D('',#506,#507,#508);
#510=CIRCLE('',#509,1.15);
#511=CARTESIAN_POINT('',(7.25493557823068,3.37133649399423,6.8));
#512=VERTEX_POINT('',#511);
#513=CARTESIAN_POINT('',(6.54713083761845,4.59729026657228,6.8));
#514=VERTEX_POINT('',#513);
#515=EDGE_CURVE('E180',#512,#514,#510,.T.);
#516=ORIENTED_EDGE('',*,*,#515,.F.);
#517=EDGE_CURVE('E193',#514,#512,#244,.F.);
#518=ORIENTED_EDGE('',*,*,#517,.F.);
#519=EDGE_LOOP('',(#516,#518));
#520=FACE_BOUND('',#519,.T.);
#521=ADVANCED_FACE('F192',(#520),#228,.T.);
#522=CARTESIAN_POINT('',(7.68597545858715,4.43750000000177,6.8));
#523=DIRECTION('',(0.,0.,1.));
#524=DIRECTION('',(0.,-1.,0.));
#525=AXIS2_PLACEMENT_3D('',#522,#523,#524);
#526=CYLINDRICAL_SURFACE('',#525,1.15);
#527=DIRECTION('',(0.,0.,1.));
#528=VECTOR('',#527,1.);
#529=CARTESIAN_POINT('',(7.25493557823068,3.37133649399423,6.8));
#530=LINE('',#529,#528);
#531=CARTESIAN_POINT('',(7.25493557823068,3.37133649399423,12.2499999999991));
#532=VERTEX_POINT('',#531);
#533=EDGE_CURVE('E177',#512,#532,#530,.T.);
#534=ORIENTED_EDGE('',*,*,#533,.F.);
#535=ORIENTED_EDGE('',*,*,#515,.T.);
#536=DIRECTION('',(0.,0.,1.));
#537=VECTOR('',#536,1.);
#538=CARTESIAN_POINT('',(6.54713083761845,4.59729026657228,6.8));
#539=LINE('',#538,#537);
#540=CARTESIAN_POINT('',(6.54713083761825,4.59729026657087,12.25));
#541=VERTEX_POINT('',#540);
#542=EDGE_CURVE('E188',#514,#541,#539,.T.);
#543=ORIENTED_EDGE('',*,*,#542,.T.);
#544=CARTESIAN_POINT('',(7.25513557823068,3.37125565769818,12.2498526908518));
#545=CARTESIAN_POINT('',(7.21043982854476,3.38931533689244,12.2827673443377));
#546=CARTESIAN_POINT('',(7.16563264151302,3.41069638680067,12.3141675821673));
#547=CARTESIAN_POINT('',(7.07658806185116,3.46087905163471,12.3725658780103));
#548=CARTESIAN_POINT('',(7.03236079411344,3.48975247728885,12.399516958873));
#549=CARTESIAN_POINT('',(6.95398075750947,3.5494413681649,12.4426442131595));
#550=CARTESIAN_POINT('',(6.91945000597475,3.57896658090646,12.459887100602));
#551=CARTESIAN_POINT('',(6.85312362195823,3.6431594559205,12.4888142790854));
#552=CARTESIAN_POINT('',(6.82131839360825,3.67780779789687,12.50051878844));
#553=CARTESIAN_POINT('',(6.76131362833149,3.75208390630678,12.5175180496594));
#554=CARTESIAN_POINT('',(6.73314735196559,3.79175182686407,12.5227569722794));
#555=CARTESIAN_POINT('',(6.68197914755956,3.87459677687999,12.5260773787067));
#556=CARTESIAN_POINT('',(6.6589784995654,3.91777467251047,12.5241570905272));
#557=CARTESIAN_POINT('',(6.62130533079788,4.00068974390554,12.5140193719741));
#558=CARTESIAN_POINT('',(6.60596809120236,4.04022639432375,12.50657703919));
#559=CARTESIAN_POINT('',(6.57998847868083,4.1196311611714,12.4868847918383));
#560=CARTESIAN_POINT('',(6.56934843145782,4.15949943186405,12.4746325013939));
#561=CARTESIAN_POINT('',(6.54956561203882,4.25286326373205,12.4409660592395));
#562=CARTESIAN_POINT('',(6.54231471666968,4.30614049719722,12.4178426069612));
#563=CARTESIAN_POINT('',(6.53510255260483,4.41038121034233,12.3660321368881));
#564=CARTESIAN_POINT('',(6.53515005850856,4.46134183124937,12.3373384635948));
#565=CARTESIAN_POINT('',(6.54019818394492,4.54025639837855,12.2883669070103));
#566=CARTESIAN_POINT('',(6.54318368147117,4.56916440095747,12.269391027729));
#567=CARTESIAN_POINT('',(6.54715891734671,4.59749026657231,12.2498620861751));
#568=B_SPLINE_CURVE_WITH_KNOTS('',3,(#544,#545,#546,#547,#548,#549,#550,#551,#552,#553,#554,
#555,#556,#557,#558,#559,#560,#561,#562,#563,#564,#565,#566,#567),.UNSPECIFIED.,.F.,.F.,(4,2,2,
2,2,2,2,2,2,2,2,4),(0.,0.175413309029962,0.352574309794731,0.497771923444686,0.642435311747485,
0.788339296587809,0.934279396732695,1.06288407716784,1.1915523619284,1.36617341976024,
1.54100441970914,1.64498267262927),.UNSPECIFIED.);
#569=EDGE_CURVE('E183',#532,#541,#568,.T.);
#570=ORIENTED_EDGE('',*,*,#569,.F.);
#571=EDGE_LOOP('',(#534,#535,#543,#570));
#572=FACE_BOUND('',#571,.T.);
#573=ADVANCED_FACE('F179',(#572),#526,.F.);
#574=CARTESIAN_POINT('',(4.43750000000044,7.68597545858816,6.8));
#575=DIRECTION('',(0.,0.,-1.));
#576=DIRECTION('',(0.,-1.,0.));
#577=AXIS2_PLACEMENT_3D('',#574,#575,#576);
#578=CIRCLE('',#577,1.15);
#579=CARTESIAN_POINT('',(4.59729026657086,6.54713083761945,6.8));
#580=VERTEX_POINT('',#579);
#581=CARTESIAN_POINT('',(3.3713364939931,7.25493557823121,6.8));
#582=VERTEX_POINT('',#581);
#583=EDGE_CURVE('E194',#580,#582,#578,.T.);
#584=ORIENTED_EDGE('',*,*,#583,.F.);
#585=EDGE_CURVE('E200',#582,#580,#244,.F.);
#586=ORIENTED_EDGE('',*,*,#585,.F.);
#587=EDGE_LOOP('',(#584,#586));
#588=FACE_BOUND('',#587,.T.);
#589=ADVANCED_FACE('F378',(#588),#228,.T.);
#590=CARTESIAN_POINT('',(4.43750000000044,7.68597545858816,6.8));
#591=DIRECTION('',(0.,0.,1.));
#592=DIRECTION('',(0.,-1.,0.));
#593=AXIS2_PLACEMENT_3D('',#590,#591,#592);
#594=CYLINDRICAL_SURFACE('',#593,1.15);
#595=DIRECTION('',(0.,0.,1.));
#596=VECTOR('',#595,1.);
#597=CARTESIAN_POINT('',(4.59729026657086,6.54713083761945,6.8));
#598=LINE('',#597,#596);
#599=CARTESIAN_POINT('',(4.59729026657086,6.54713083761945,12.2499999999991));
#600=VERTEX_POINT('',#599);
#601=EDGE_CURVE('E326',#580,#600,#598,.T.);
#602=ORIENTED_EDGE('',*,*,#601,.F.);
#603=ORIENTED_EDGE('',*,*,#583,.T.);
#604=DIRECTION('',(0.,0.,1.));
#605=VECTOR('',#604,1.);
#606=CARTESIAN_POINT('',(3.3713364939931,7.25493557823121,6.8));
#607=LINE('',#606,#605);
#608=CARTESIAN_POINT('',(3.37133649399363,7.25493557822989,12.25));
#609=VERTEX_POINT('',#608);
#610=EDGE_CURVE('E324',#582,#609,#607,.T.);
#611=ORIENTED_EDGE('',*,*,#610,.T.);
#612=CARTESIAN_POINT('',(4.59749026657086,6.54715891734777,12.249862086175));
#613=CARTESIAN_POINT('',(4.5497531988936,6.5404518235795,12.2827759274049));
#614=CARTESIAN_POINT('',(4.50025899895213,6.53656536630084,12.3141753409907));
#615=CARTESIAN_POINT('',(4.39805391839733,6.53550363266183,12.3725719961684));
#616=CARTESIAN_POINT('',(4.34531590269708,6.53839560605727,12.3995222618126));
#617=CARTESIAN_POINT('',(4.2475932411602,6.5508984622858,12.4426482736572));
#618=CARTESIAN_POINT('',(4.20292634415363,6.55920303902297,12.4598906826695));
#619=CARTESIAN_POINT('',(4.11339009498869,6.5816331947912,12.4888168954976));
#620=CARTESIAN_POINT('',(4.06852209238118,6.59573724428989,12.5005209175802));
#621=CARTESIAN_POINT('',(3.97941910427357,6.63006040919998,12.517519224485));
#622=CARTESIAN_POINT('',(3.9351928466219,6.65033092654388,12.5227576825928));
#623=CARTESIAN_POINT('',(3.84945829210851,6.69649299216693,12.526077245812));
#624=CARTESIAN_POINT('',(3.80795067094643,6.72238593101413,12.5241565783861));
#625=CARTESIAN_POINT('',(3.73386792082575,6.77535612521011,12.5140182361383));
#626=CARTESIAN_POINT('',(3.70081740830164,6.80192739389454,12.5065756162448));
#627=CARTESIAN_POINT('',(3.63861654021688,6.85770436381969,12.4868828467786));
#628=CARTESIAN_POINT('',(3.60946812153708,6.88691136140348,12.4746303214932));
#629=CARTESIAN_POINT('',(3.54565408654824,6.95787590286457,12.4409632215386));
#630=CARTESIAN_POINT('',(3.51273611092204,7.00039031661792,12.4178393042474));
#631=CARTESIAN_POINT('',(3.45437012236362,7.08706015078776,12.3660279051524));
#632=CARTESIAN_POINT('',(3.42893113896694,7.13121748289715,12.3373337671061));
#633=CARTESIAN_POINT('',(3.39384524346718,7.20208570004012,12.2883604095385));
#634=CARTESIAN_POINT('',(3.38197627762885,7.22861528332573,12.2693831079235));
#635=CARTESIAN_POINT('',(3.37125565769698,7.25513557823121,12.2498526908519));
#636=B_SPLINE_CURVE_WITH_KNOTS('',3,(#612,#613,#614,#615,#616,#617,#618,#619,#620,#621,#622,
#623,#624,#625,#626,#627,#628,#629,#630,#631,#632,#633,#634,#635),.UNSPECIFIED.,.F.,.F.,(4,2,2,
2,2,2,2,2,2,2,2,4),(0.,0.175410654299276,0.35256893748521,0.497765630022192,0.642428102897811,
0.788331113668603,0.934270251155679,1.06287477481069,1.19154289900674,1.36616525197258,
1.54099757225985,1.64498268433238),.UNSPECIFIED.);
#637=EDGE_CURVE('E364',#600,#609,#636,.T.);
#638=ORIENTED_EDGE('',*,*,#637,.F.);
#639=EDGE_LOOP('',(#602,#603,#611,#638));
#640=FACE_BOUND('',#639,.T.);
#641=ADVANCED_FACE('F379',(#640),#594,.F.);
#642=CARTESIAN_POINT('',(9.3198018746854E-13,8.8750000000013,6.8));
#643=DIRECTION('',(0.,0.,-1.));
#644=DIRECTION('',(0.,-1.,0.));
#645=AXIS2_PLACEMENT_3D('',#642,#643,#644);
#646=CIRCLE('',#645,1.15);
#647=CARTESIAN_POINT('',(0.707804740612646,7.96862676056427,6.8));
#648=VERTEX_POINT('',#647);
#649=CARTESIAN_POINT('',(-0.707804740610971,7.96862676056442,6.8));
#650=VERTEX_POINT('',#649);
#651=EDGE_CURVE('E255',#648,#650,#646,.T.);
#652=ORIENTED_EDGE('',*,*,#651,.F.);
#653=EDGE_CURVE('E205',#650,#648,#244,.F.);
#654=ORIENTED_EDGE('',*,*,#653,.F.);
#655=EDGE_LOOP('',(#652,#654));
#656=FACE_BOUND('',#655,.T.);
#657=ADVANCED_FACE('F254',(#656),#228,.T.);
#658=CARTESIAN_POINT('',(9.3198018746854E-13,8.8750000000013,6.8));
#659=DIRECTION('',(0.,0.,1.));
#660=DIRECTION('',(0.,-1.,0.));
#661=AXIS2_PLACEMENT_3D('',#658,#659,#660);
#662=CYLINDRICAL_SURFACE('',#661,1.15);
#663=DIRECTION('',(0.,0.,1.));
#664=VECTOR('',#663,1.);
#665=CARTESIAN_POINT('',(0.707804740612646,7.96862676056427,6.8));
#666=LINE('',#665,#664);
#667=CARTESIAN_POINT('',(0.707804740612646,7.96862676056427,12.2499999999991));
#668=VERTEX_POINT('',#667);
#669=EDGE_CURVE('E249',#648,#668,#666,.T.);
#670=ORIENTED_EDGE('',*,*,#669,.F.);
#671=ORIENTED_EDGE('',*,*,#651,.T.);
#672=DIRECTION('',(0.,0.,1.));
#673=VECTOR('',#672,1.);
#674=CARTESIAN_POINT('',(-0.707804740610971,7.96862676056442,6.8));
#675=LINE('',#674,#673);
#676=CARTESIAN_POINT('',(-0.707804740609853,7.96862676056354,12.25));
#677=VERTEX_POINT('',#676);
#678=EDGE_CURVE('E29',#650,#677,#675,.T.);
#679=ORIENTED_EDGE('',*,*,#678,.T.);
#680=CARTESIAN_POINT('',(0.708004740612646,7.96878298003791,12.2498266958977));
#681=CARTESIAN_POINT('',(0.670016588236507,7.93910304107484,12.2827435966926));
#682=CARTESIAN_POINT('',(0.629096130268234,7.9109872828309,12.3141461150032));
#683=CARTESIAN_POINT('',(0.541113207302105,7.85895957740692,12.372548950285));
#684=CARTESIAN_POINT('',(0.493993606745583,7.83509230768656,12.3995022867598));
#685=CARTESIAN_POINT('',(0.403110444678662,7.79705455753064,12.4426329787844));
#686=CARTESIAN_POINT('',(0.360275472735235,7.78191147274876,12.4598771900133));
#687=CARTESIAN_POINT('',(0.271519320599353,7.7565652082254,12.4888070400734));
#688=CARTESIAN_POINT('',(0.225610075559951,7.74634405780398,12.5005128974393));
#689=CARTESIAN_POINT('',(0.131281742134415,7.73151414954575,12.5175147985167));
#690=CARTESIAN_POINT('',(0.0828445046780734,7.72695427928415,12.5227550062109));
#691=CARTESIAN_POINT('',(-0.0144870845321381,7.72406175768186,12.5260777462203));
#692=CARTESIAN_POINT('',(-0.0633815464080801,7.7257306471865,12.5241585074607));
#693=CARTESIAN_POINT('',(-0.154026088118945,7.73456075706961,12.5140225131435));
#694=CARTESIAN_POINT('',(-0.195934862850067,7.74104594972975,12.5065809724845));
#695=CARTESIAN_POINT('',(-0.277692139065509,7.75824805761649,12.4868901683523));
#696=CARTESIAN_POINT('',(-0.317539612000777,7.76896706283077,12.4746385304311));
#697=CARTESIAN_POINT('',(-0.40828645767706,7.79851491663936,12.4409739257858));
#698=CARTESIAN_POINT('',(-0.458050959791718,7.81887290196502,12.4178517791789));
#699=CARTESIAN_POINT('',(-0.551931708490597,7.86474498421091,12.3660439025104));
#700=CARTESIAN_POINT('',(-0.596041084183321,7.89026525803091,12.3373515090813));
#701=CARTESIAN_POINT('',(-0.66188083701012,7.93410696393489,12.2883657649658));
#702=CARTESIAN_POINT('',(-0.685443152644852,7.95116148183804,12.2693731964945));
#703=CARTESIAN_POINT('',(-0.708004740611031,7.96878298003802,12.2498266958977));
#704=B_SPLINE_CURVE_WITH_KNOTS('',3,(#680,#681,#682,#683,#684,#685,#686,#687,#688,#689,#690,
#691,#692,#693,#694,#695,#696,#697,#698,#699,#700,#701,#702,#703),.UNSPECIFIED.,.F.,.F.,(4,2,2,
2,2,2,2,2,2,2,2,4),(0.,0.175420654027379,0.352589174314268,0.497789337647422,0.642455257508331,
0.788361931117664,0.934304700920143,1.06290984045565,1.19157854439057,1.3661958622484,
1.54102336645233,1.64509140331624),.UNSPECIFIED.);
#705=EDGE_CURVE('E566',#668,#677,#704,.T.);
#706=ORIENTED_EDGE('',*,*,#705,.F.);
#707=EDGE_LOOP('',(#670,#671,#679,#706));
#708=FACE_BOUND('',#707,.T.);
#709=ADVANCED_FACE('F256',(#708),#662,.F.);
#710=CARTESIAN_POINT('',(-4.43749999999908,7.6859754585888,6.8));
#711=DIRECTION('',(0.,0.,-1.));
#712=DIRECTION('',(0.,-1.,0.));
#713=AXIS2_PLACEMENT_3D('',#710,#711,#712);
#714=CIRCLE('',#713,1.14999999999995);
#715=CARTESIAN_POINT('',(-3.37133649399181,7.25493557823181,6.8));
#716=VERTEX_POINT('',#715);
#717=CARTESIAN_POINT('',(-4.5972902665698,6.54713083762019,6.8));
#718=VERTEX_POINT('',#717);
#719=EDGE_CURVE('E257',#716,#718,#714,.T.);
#720=ORIENTED_EDGE('',*,*,#719,.F.);
#721=EDGE_CURVE('E241',#718,#716,#244,.F.);
#722=ORIENTED_EDGE('',*,*,#721,.F.);
#723=EDGE_LOOP('',(#720,#722));
#724=FACE_BOUND('',#723,.T.);
#725=ADVANCED_FACE('F559',(#724),#228,.T.);
#726=CARTESIAN_POINT('',(-4.43749999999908,7.6859754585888,6.8));
#727=DIRECTION('',(0.,0.,1.));
#728=DIRECTION('',(0.,-1.,0.));
#729=AXIS2_PLACEMENT_3D('',#726,#727,#728);
#730=CYLINDRICAL_SURFACE('',#729,1.14999999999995);
#731=DIRECTION('',(0.,0.,1.));
#732=VECTOR('',#731,1.);
#733=CARTESIAN_POINT('',(-3.37133649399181,7.25493557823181,6.8));
#734=LINE('',#733,#732);
#735=CARTESIAN_POINT('',(-3.37133649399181,7.25493557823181,12.2499999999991));
#736=VERTEX_POINT('',#735);
#737=EDGE_CURVE('E320',#716,#736,#734,.T.);
#738=ORIENTED_EDGE('',*,*,#737,.F.);
#739=ORIENTED_EDGE('',*,*,#719,.T.);
#740=DIRECTION('',(0.,0.,1.));
#741=VECTOR('',#740,1.);
#742=CARTESIAN_POINT('',(-4.5972902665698,6.54713083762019,6.8));
#743=LINE('',#742,#741);
#744=CARTESIAN_POINT('',(-4.5972902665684,6.54713083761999,12.25));
#745=VERTEX_POINT('',#744);
#746=EDGE_CURVE('E37',#718,#745,#743,.T.);
#747=ORIENTED_EDGE('',*,*,#746,.T.);
#748=CARTESIAN_POINT('',(-3.37125565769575,7.25513557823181,12.2498526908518));
#749=CARTESIAN_POINT('',(-3.38931533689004,7.21043982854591,12.2827673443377));
#750=CARTESIAN_POINT('',(-3.41069638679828,7.16563264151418,12.3141675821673));
#751=CARTESIAN_POINT('',(-3.46087905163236,7.07658806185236,12.3725658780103));
#752=CARTESIAN_POINT('',(-3.48975247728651,7.03236079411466,12.3995169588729));
#753=CARTESIAN_POINT('',(-3.54944136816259,6.95398075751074,12.4426442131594));
#754=CARTESIAN_POINT('',(-3.57896658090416,6.91945000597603,12.4598871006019));
#755=CARTESIAN_POINT('',(-3.64315945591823,6.85312362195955,12.4888142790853));
#756=CARTESIAN_POINT('',(-3.67780779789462,6.8213183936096,12.5005187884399));
#757=CARTESIAN_POINT('',(-3.75208390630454,6.76131362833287,12.5175180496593));
#758=CARTESIAN_POINT('',(-3.79175182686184,6.73314735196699,12.5227569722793));
#759=CARTESIAN_POINT('',(-3.87459677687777,6.68197914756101,12.5260773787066));
#760=CARTESIAN_POINT('',(-3.91777467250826,6.65897849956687,12.5241570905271));
#761=CARTESIAN_POINT('',(-4.00068974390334,6.62130533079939,12.514019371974));
#762=CARTESIAN_POINT('',(-4.04022639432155,6.60596809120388,12.5065770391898));
#763=CARTESIAN_POINT('',(-4.11963116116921,6.57998847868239,12.4868847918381));
#764=CARTESIAN_POINT('',(-4.15949943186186,6.5693484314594,12.4746325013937));
#765=CARTESIAN_POINT('',(-4.25286326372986,6.54956561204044,12.4409660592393));
#766=CARTESIAN_POINT('',(-4.30614049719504,6.54231471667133,12.417842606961));
#767=CARTESIAN_POINT('',(-4.41038121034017,6.53510255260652,12.3660321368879));
#768=CARTESIAN_POINT('',(-4.4613418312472,6.53515005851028,12.3373384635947));
#769=CARTESIAN_POINT('',(-4.54025639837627,6.54019818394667,12.2883669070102));
#770=CARTESIAN_POINT('',(-4.56916440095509,6.54318368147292,12.269391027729));
#771=CARTESIAN_POINT('',(-4.59749026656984,6.54715891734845,12.2498620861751));
#772=B_SPLINE_CURVE_WITH_KNOTS('',3,(#748,#749,#750,#751,#752,#753,#754,#755,#756,#757,#758,
#759,#760,#761,#762,#763,#764,#765,#766,#767,#768,#769,#770,#771),.UNSPECIFIED.,.F.,.F.,(4,2,2,
2,2,2,2,2,2,2,2,4),(0.,0.175413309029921,0.352574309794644,0.497771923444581,0.642435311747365,
0.788339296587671,0.934279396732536,1.06288407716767,1.19155236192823,1.36617341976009,
1.54100441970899,1.64498267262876),.UNSPECIFIED.);
#773=EDGE_CURVE('E561',#736,#745,#772,.T.);
#774=ORIENTED_EDGE('',*,*,#773,.F.);
#775=EDGE_LOOP('',(#738,#739,#747,#774));
#776=FACE_BOUND('',#775,.T.);
#777=ADVANCED_FACE('F556',(#776),#730,.F.);
#778=CARTESIAN_POINT('',(-7.68597545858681,4.4375000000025,6.8));
#779=DIRECTION('',(0.,0.,-1.));
#780=DIRECTION('',(0.,-1.,0.));
#781=AXIS2_PLACEMENT_3D('',#778,#779,#780);
#782=CIRCLE('',#781,1.15);
#783=CARTESIAN_POINT('',(-6.54713083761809,4.59729026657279,6.8));
#784=VERTEX_POINT('',#783);
#785=CARTESIAN_POINT('',(-7.25493557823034,3.37133649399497,6.8));
#786=VERTEX_POINT('',#785);
#787=EDGE_CURVE('E259',#784,#786,#782,.T.);
#788=ORIENTED_EDGE('',*,*,#787,.F.);
#789=EDGE_CURVE('E237',#786,#784,#244,.F.);
#790=ORIENTED_EDGE('',*,*,#789,.F.);
#791=EDGE_LOOP('',(#788,#790));
#792=FACE_BOUND('',#791,.T.);
#793=ADVANCED_FACE('F554',(#792),#228,.T.);
#794=CARTESIAN_POINT('',(-7.68597545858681,4.4375000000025,6.8));
#795=DIRECTION('',(0.,0.,1.));
#796=DIRECTION('',(0.,-1.,0.));
#797=AXIS2_PLACEMENT_3D('',#794,#795,#796);
#798=CYLINDRICAL_SURFACE('',#797,1.15);
#799=DIRECTION('',(0.,0.,1.));
#800=VECTOR('',#799,1.);
#801=CARTESIAN_POINT('',(-6.54713083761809,4.59729026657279,6.8));
#802=LINE('',#801,#800);
#803=CARTESIAN_POINT('',(-6.54713083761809,4.59729026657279,12.2499999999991));
#804=VERTEX_POINT('',#803);
#805=EDGE_CURVE('E317',#784,#804,#802,.T.);
#806=ORIENTED_EDGE('',*,*,#805,.F.);
#807=ORIENTED_EDGE('',*,*,#787,.T.);
#808=DIRECTION('',(0.,0.,1.));
#809=VECTOR('',#808,1.);
#810=CARTESIAN_POINT('',(-7.25493557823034,3.37133649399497,6.8));
#811=LINE('',#810,#809);
#812=CARTESIAN_POINT('',(-7.25493557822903,3.3713364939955,12.25));
#813=VERTEX_POINT('',#812);
#814=EDGE_CURVE('E315',#786,#813,#811,.T.);
#815=ORIENTED_EDGE('',*,*,#814,.T.);
#816=CARTESIAN_POINT('',(-6.54715891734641,4.59749026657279,12.249862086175));
#817=CARTESIAN_POINT('',(-6.54045182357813,4.54975319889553,12.2827759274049));
#818=CARTESIAN_POINT('',(-6.53656536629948,4.50025899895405,12.3141753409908));
#819=CARTESIAN_POINT('',(-6.53550363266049,4.39805391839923,12.3725719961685));
#820=CARTESIAN_POINT('',(-6.53839560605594,4.34531590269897,12.3995222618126));
#821=CARTESIAN_POINT('',(-6.55089846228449,4.24759324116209,12.4426482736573));
#822=CARTESIAN_POINT('',(-6.55920303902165,4.20292634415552,12.4598906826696));
#823=CARTESIAN_POINT('',(-6.5816331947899,4.11339009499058,12.4888168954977));
#824=CARTESIAN_POINT('',(-6.5957372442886,4.06852209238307,12.5005209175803));
#825=CARTESIAN_POINT('',(-6.6300604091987,3.97941910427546,12.5175192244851));
#826=CARTESIAN_POINT('',(-6.65033092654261,3.93519284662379,12.522757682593));
#827=CARTESIAN_POINT('',(-6.69649299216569,3.84945829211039,12.5260772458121));
#828=CARTESIAN_POINT('',(-6.7223859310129,3.80795067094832,12.5241565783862));
#829=CARTESIAN_POINT('',(-6.7753561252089,3.73386792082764,12.5140182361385));
#830=CARTESIAN_POINT('',(-6.80192739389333,3.70081740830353,12.506575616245));
#831=CARTESIAN_POINT('',(-6.85770436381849,3.63861654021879,12.4868828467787));
#832=CARTESIAN_POINT('',(-6.88691136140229,3.60946812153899,12.4746303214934));
#833=CARTESIAN_POINT('',(-6.95787590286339,3.54565408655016,12.4409632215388));
#834=CARTESIAN_POINT('',(-7.00039031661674,3.51273611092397,12.4178393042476));
#835=CARTESIAN_POINT('',(-7.08706015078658,3.45437012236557,12.3660279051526));
#836=CARTESIAN_POINT('',(-7.13121748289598,3.4289311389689,12.3373337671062));
#837=CARTESIAN_POINT('',(-7.20208570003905,3.39384524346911,12.2883604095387));
#838=CARTESIAN_POINT('',(-7.22861528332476,3.38197627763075,12.2693831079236));
#839=CARTESIAN_POINT('',(-7.25513557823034,3.37125565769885,12.2498526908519));
#840=B_SPLINE_CURVE_WITH_KNOTS('',3,(#816,#817,#818,#819,#820,#821,#822,#823,#824,#825,#826,
#827,#828,#829,#830,#831,#832,#833,#834,#835,#836,#837,#838,#839),.UNSPECIFIED.,.F.,.F.,(4,2,2,
2,2,2,2,2,2,2,2,4),(0.,0.17541065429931,0.352568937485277,0.497765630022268,0.642428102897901,
0.788331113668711,0.934270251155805,1.06287477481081,1.19154289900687,1.36616525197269,
1.54099757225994,1.64498268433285),.UNSPECIFIED.);
#841=EDGE_CURVE('E537',#804,#813,#840,.T.);
#842=ORIENTED_EDGE('',*,*,#841,.F.);
#843=EDGE_LOOP('',(#806,#807,#815,#842));
#844=FACE_BOUND('',#843,.T.);
#845=ADVANCED_FACE('F550',(#844),#798,.F.);
#846=CARTESIAN_POINT('',(-8.8750000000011,2.03049382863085E-12,6.8));
#847=DIRECTION('',(0.,0.,-1.));
#848=DIRECTION('',(0.,-1.,0.));
#849=AXIS2_PLACEMENT_3D('',#846,#847,#848);
#850=CIRCLE('',#849,1.15);
#851=CARTESIAN_POINT('',(-7.96862676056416,0.707804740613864,6.8));
#852=VERTEX_POINT('',#851);
#853=CARTESIAN_POINT('',(-7.96862676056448,-0.707804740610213,6.8));
#854=VERTEX_POINT('',#853);
#855=EDGE_CURVE('E266',#852,#854,#850,.T.);
#856=ORIENTED_EDGE('',*,*,#855,.F.);
#857=EDGE_CURVE('E233',#854,#852,#244,.F.);
#858=ORIENTED_EDGE('',*,*,#857,.F.);
#859=EDGE_LOOP('',(#856,#858));
#860=FACE_BOUND('',#859,.T.);
#861=ADVANCED_FACE('F548',(#860),#228,.T.);
#862=CARTESIAN_POINT('',(-8.8750000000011,2.03049382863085E-12,6.8));
#863=DIRECTION('',(0.,0.,1.));
#864=DIRECTION('',(0.,-1.,0.));
#865=AXIS2_PLACEMENT_3D('',#862,#863,#864);
#866=CYLINDRICAL_SURFACE('',#865,1.15);
#867=DIRECTION('',(0.,0.,1.));
#868=VECTOR('',#867,1.);
#869=CARTESIAN_POINT('',(-7.96862676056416,0.707804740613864,6.8));
#870=LINE('',#869,#868);
#871=CARTESIAN_POINT('',(-7.96862676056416,0.707804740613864,12.2499999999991));
#872=VERTEX_POINT('',#871);
#873=EDGE_CURVE('E313',#852,#872,#870,.T.);
#874=ORIENTED_EDGE('',*,*,#873,.F.);
#875=ORIENTED_EDGE('',*,*,#855,.T.);
#876=DIRECTION('',(0.,0.,1.));
#877=VECTOR('',#876,1.);
#878=CARTESIAN_POINT('',(-7.96862676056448,-0.707804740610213,6.8));
#879=LINE('',#878,#877);
#880=CARTESIAN_POINT('',(-7.96862676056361,-0.707804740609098,12.25));
#881=VERTEX_POINT('',#880);
#882=EDGE_CURVE('E311',#854,#881,#879,.T.);
#883=ORIENTED_EDGE('',*,*,#882,.T.);
#884=CARTESIAN_POINT('',(-7.9687829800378,0.708004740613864,12.2498266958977));
#885=CARTESIAN_POINT('',(-7.93910304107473,0.670016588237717,12.2827435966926));
#886=CARTESIAN_POINT('',(-7.91098728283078,0.629096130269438,12.3141461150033));
#887=CARTESIAN_POINT('',(-7.85895957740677,0.541113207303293,12.3725489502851));
#888=CARTESIAN_POINT('',(-7.83509230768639,0.493993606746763,12.3995022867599));
#889=CARTESIAN_POINT('',(-7.79705455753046,0.403110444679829,12.4426329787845));
#890=CARTESIAN_POINT('',(-7.78191147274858,0.360275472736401,12.4598771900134));
#891=CARTESIAN_POINT('',(-7.75656520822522,0.271519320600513,12.4888070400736));
#892=CARTESIAN_POINT('',(-7.74634405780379,0.225610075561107,12.5005128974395));
#893=CARTESIAN_POINT('',(-7.73151414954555,0.131281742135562,12.5175147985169));
#894=CARTESIAN_POINT('',(-7.72695427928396,0.0828445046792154,12.5227550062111));
#895=CARTESIAN_POINT('',(-7.72406175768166,-0.0144870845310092,12.5260777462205));
#896=CARTESIAN_POINT('',(-7.72573064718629,-0.0633815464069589,12.5241585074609));
#897=CARTESIAN_POINT('',(-7.7345607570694,-0.154026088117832,12.5140225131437));
#898=CARTESIAN_POINT('',(-7.74104594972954,-0.195934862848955,12.5065809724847));
#899=CARTESIAN_POINT('',(-7.75824805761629,-0.277692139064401,12.4868901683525));
#900=CARTESIAN_POINT('',(-7.76896706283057,-0.317539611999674,12.4746385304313));
#901=CARTESIAN_POINT('',(-7.79851491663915,-0.408286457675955,12.4409739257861));
#902=CARTESIAN_POINT('',(-7.81887290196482,-0.458050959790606,12.4178517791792));
#903=CARTESIAN_POINT('',(-7.8647449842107,-0.551931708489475,12.3660439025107));
#904=CARTESIAN_POINT('',(-7.89026525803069,-0.596041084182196,12.3373515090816));
#905=CARTESIAN_POINT('',(-7.93410696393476,-0.661880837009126,12.288365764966));
#906=CARTESIAN_POINT('',(-7.951161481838,-0.685443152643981,12.2693731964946));
#907=CARTESIAN_POINT('',(-7.96878298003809,-0.708004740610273,12.2498266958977));
#908=B_SPLINE_CURVE_WITH_KNOTS('',3,(#884,#885,#886,#887,#888,#889,#890,#891,#892,#893,#894,
#895,#896,#897,#898,#899,#900,#901,#902,#903,#904,#905,#906,#907),.UNSPECIFIED.,.F.,.F.,(4,2,2,
2,2,2,2,2,2,2,2,4),(0.,0.175420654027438,0.352589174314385,0.497789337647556,0.642455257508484,
0.788361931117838,0.934304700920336,1.06290984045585,1.19157854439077,1.36619586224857,
1.54102336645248,1.64509140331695),.UNSPECIFIED.);
#909=EDGE_CURVE('E530',#872,#881,#908,.T.);
#910=ORIENTED_EDGE('',*,*,#909,.F.);
#911=EDGE_LOOP('',(#874,#875,#883,#910));
#912=FACE_BOUND('',#911,.T.);
#913=ADVANCED_FACE('F544',(#912),#866,.F.);
#914=CARTESIAN_POINT('',(-7.68597545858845,-4.43749999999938,6.8));
#915=DIRECTION('',(0.,0.,-1.));
#916=DIRECTION('',(0.,-1.,0.));
#917=AXIS2_PLACEMENT_3D('',#914,#915,#916);
#918=CIRCLE('',#917,1.15);
#919=CARTESIAN_POINT('',(-7.25493557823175,-3.37133649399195,6.8));
#920=VERTEX_POINT('',#919);
#921=CARTESIAN_POINT('',(-6.54713083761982,-4.59729026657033,6.8));
#922=VERTEX_POINT('',#921);
#923=EDGE_CURVE('E269',#920,#922,#918,.T.);
#924=ORIENTED_EDGE('',*,*,#923,.F.);
#925=EDGE_CURVE('E230',#922,#920,#244,.F.);
#926=ORIENTED_EDGE('',*,*,#925,.F.);
#927=EDGE_LOOP('',(#924,#926));
#928=FACE_BOUND('',#927,.T.);
#929=ADVANCED_FACE('F547',(#928),#228,.T.);
#930=CARTESIAN_POINT('',(-7.68597545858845,-4.43749999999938,6.8));
#931=DIRECTION('',(0.,0.,1.));
#932=DIRECTION('',(0.,-1.,0.));
#933=AXIS2_PLACEMENT_3D('',#930,#931,#932);
#934=CYLINDRICAL_SURFACE('',#933,1.15);
#935=DIRECTION('',(0.,0.,1.));
#936=VECTOR('',#935,1.);
#937=CARTESIAN_POINT('',(-7.25493557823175,-3.37133649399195,6.8));
#938=LINE('',#937,#936);
#939=CARTESIAN_POINT('',(-7.25493557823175,-3.37133649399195,12.2499999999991));
#940=VERTEX_POINT('',#939);
#941=EDGE_CURVE('E309',#920,#940,#938,.T.);
#942=ORIENTED_EDGE('',*,*,#941,.F.);
#943=ORIENTED_EDGE('',*,*,#923,.T.);
#944=DIRECTION('',(0.,0.,1.));
#945=VECTOR('',#944,1.);
#946=CARTESIAN_POINT('',(-6.54713083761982,-4.59729026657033,6.8));
#947=LINE('',#946,#945);
#948=CARTESIAN_POINT('',(-6.54713083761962,-4.59729026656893,12.25));
#949=VERTEX_POINT('',#948);
#950=EDGE_CURVE('E307',#922,#949,#947,.T.);
#951=ORIENTED_EDGE('',*,*,#950,.T.);
#952=CARTESIAN_POINT('',(-7.25513557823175,-3.37125565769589,12.2498526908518));
#953=CARTESIAN_POINT('',(-7.21043982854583,-3.38931533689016,12.2827673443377));
#954=CARTESIAN_POINT('',(-7.16563264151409,-3.4106963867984,12.3141675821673));
#955=CARTESIAN_POINT('',(-7.07658806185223,-3.46087905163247,12.3725658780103));
#956=CARTESIAN_POINT('',(-7.03236079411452,-3.48975247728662,12.399516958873));
#957=CARTESIAN_POINT('',(-6.95398075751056,-3.5494413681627,12.4426442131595));
#958=CARTESIAN_POINT('',(-6.91945000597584,-3.57896658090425,12.4598871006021));
#959=CARTESIAN_POINT('',(-6.85312362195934,-3.64315945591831,12.4888142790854));
#960=CARTESIAN_POINT('',(-6.82131839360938,-3.6778077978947,12.50051878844));
#961=CARTESIAN_POINT('',(-6.76131362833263,-3.75208390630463,12.5175180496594));
#962=CARTESIAN_POINT('',(-6.73314735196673,-3.79175182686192,12.5227569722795));
#963=CARTESIAN_POINT('',(-6.68197914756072,-3.87459677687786,12.5260773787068));
#964=CARTESIAN_POINT('',(-6.65897849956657,-3.91777467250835,12.5241570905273));
#965=CARTESIAN_POINT('',(-6.62130533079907,-4.00068974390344,12.5140193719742));
#966=CARTESIAN_POINT('',(-6.60596809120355,-4.04022639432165,12.5065770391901));
#967=CARTESIAN_POINT('',(-6.57998847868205,-4.11963116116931,12.4868847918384));
#968=CARTESIAN_POINT('',(-6.56934843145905,-4.15949943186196,12.474632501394));
#969=CARTESIAN_POINT('',(-6.54956561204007,-4.25286326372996,12.4409660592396));
#970=CARTESIAN_POINT('',(-6.54231471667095,-4.30614049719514,12.4178426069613));
#971=CARTESIAN_POINT('',(-6.53510255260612,-4.41038121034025,12.3660321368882));
#972=CARTESIAN_POINT('',(-6.53515005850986,-4.46134183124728,12.3373384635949));
#973=CARTESIAN_POINT('',(-6.54019818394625,-4.5402563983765,12.2883669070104));
#974=CARTESIAN_POINT('',(-6.54318368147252,-4.56916440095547,12.2693910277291));
#975=CARTESIAN_POINT('',(-6.54715891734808,-4.59749026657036,12.2498620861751));
#976=B_SPLINE_CURVE_WITH_KNOTS('',3,(#952,#953,#954,#955,#956,#957,#958,#959,#960,#961,#962,
#963,#964,#965,#966,#967,#968,#969,#970,#971,#972,#973,#974,#975),.UNSPECIFIED.,.F.,.F.,(4,2,2,
2,2,2,2,2,2,2,2,4),(0.,0.175413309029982,0.352574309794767,0.497771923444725,0.642435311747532,
0.788339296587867,0.934279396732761,1.0628840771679,1.19155236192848,1.36617341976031,
1.54100441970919,1.64498267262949),.UNSPECIFIED.);
#977=EDGE_CURVE('E523',#940,#949,#976,.T.);
#978=ORIENTED_EDGE('',*,*,#977,.F.);
#979=EDGE_LOOP('',(#942,#943,#951,#978));
#980=FACE_BOUND('',#979,.T.);
#981=ADVANCED_FACE('F513',(#980),#934,.F.);
#982=CARTESIAN_POINT('',(0.,0.,12.25));
#983=DIRECTION('',(0.,0.,-1.));
#984=DIRECTION('',(0.,1.,0.));
#985=AXIS2_PLACEMENT_3D('',#982,#983,#984);
#986=CONICAL_SURFACE('',#985,8.,0.785398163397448);
#987=ORIENTED_EDGE('',*,*,#219,.T.);
#988=EDGE_LOOP('',(#987));
#989=FACE_BOUND('',#988,.T.);
#990=CARTESIAN_POINT('',(0.,0.,12.25));
#991=DIRECTION('',(0.,0.,-1.));
#992=DIRECTION('',(0.,1.,0.));
#993=AXIS2_PLACEMENT_3D('',#990,#991,#992);
#994=CIRCLE('',#993,8.);
#995=EDGE_CURVE('E647',#464,#405,#994,.T.);
#996=ORIENTED_EDGE('',*,*,#995,.F.);
#997=ORIENTED_EDGE('',*,*,#501,.T.);
#998=EDGE_CURVE('E650',#532,#473,#994,.T.);
#999=ORIENTED_EDGE('',*,*,#998,.F.);
#1000=ORIENTED_EDGE('',*,*,#569,.T.);
#1001=EDGE_CURVE('E345',#600,#541,#994,.T.);
#1002=ORIENTED_EDGE('',*,*,#1001,.F.);
#1003=ORIENTED_EDGE('',*,*,#637,.T.);
#1004=EDGE_CURVE('E342',#668,#609,#994,.T.);
#1005=ORIENTED_EDGE('',*,*,#1004,.F.);
#1006=ORIENTED_EDGE('',*,*,#705,.T.);
#1007=EDGE_CURVE('E341',#736,#677,#994,.T.);
#1008=ORIENTED_EDGE('',*,*,#1007,.F.);
#1009=ORIENTED_EDGE('',*,*,#773,.T.);
#1010=EDGE_CURVE('E640',#804,#745,#994,.T.);
#1011=ORIENTED_EDGE('',*,*,#1010,.F.);
#1012=ORIENTED_EDGE('',*,*,#841,.T.);
#1013=EDGE_CURVE('E637',#872,#813,#994,.T.);
#1014=ORIENTED_EDGE('',*,*,#1013,.F.);
#1015=ORIENTED_EDGE('',*,*,#909,.T.);
#1016=EDGE_CURVE('E634',#940,#881,#994,.T.);
#1017=ORIENTED_EDGE('',*,*,#1016,.F.);
#1018=ORIENTED_EDGE('',*,*,#977,.T.);
#1019=CARTESIAN_POINT('',(-4.59729026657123,-6.54713083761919,12.2499999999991));
#1020=VERTEX_POINT('',#1019);
#1021=EDGE_CURVE('E630',#1020,#949,#994,.T.);
#1022=ORIENTED_EDGE('',*,*,#1021,.F.);
#1023=CARTESIAN_POINT('',(-4.59749026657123,-6.5471589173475,12.249862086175));
#1024=CARTESIAN_POINT('',(-4.54975319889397,-6.54045182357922,12.2827759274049));
#1025=CARTESIAN_POINT('',(-4.50025899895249,-6.53656536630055,12.3141753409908));
#1026=CARTESIAN_POINT('',(-4.39805391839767,-6.53550363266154,12.3725719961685));
#1027=CARTESIAN_POINT('',(-4.34531590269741,-6.53839560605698,12.3995222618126));
#1028=CARTESIAN_POINT('',(-4.24759324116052,-6.5508984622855,12.4426482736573));
#1029=CARTESIAN_POINT('',(-4.20292634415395,-6.55920303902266,12.4598906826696));
#1030=CARTESIAN_POINT('',(-4.113390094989,-6.58163319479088,12.4888168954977));
#1031=CARTESIAN_POINT('',(-4.06852209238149,-6.59573724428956,12.5005209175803));
#1032=CARTESIAN_POINT('',(-3.97941910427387,-6.63006040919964,12.5175192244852));
#1033=CARTESIAN_POINT('',(-3.93519284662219,-6.65033092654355,12.522757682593));
#1034=CARTESIAN_POINT('',(-3.84945829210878,-6.6964929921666,12.5260772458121));
#1035=CARTESIAN_POINT('',(-3.8079506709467,-6.7223859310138,12.5241565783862));
#1036=CARTESIAN_POINT('',(-3.73386792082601,-6.77535612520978,12.5140182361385));
#1037=CARTESIAN_POINT('',(-3.7008174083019,-6.80192739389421,12.506575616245));
#1038=CARTESIAN_POINT('',(-3.63861654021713,-6.85770436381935,12.4868828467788));
#1039=CARTESIAN_POINT('',(-3.60946812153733,-6.88691136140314,12.4746303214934));
#1040=CARTESIAN_POINT('',(-3.54565408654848,-6.95787590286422,12.4409632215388));
#1041=CARTESIAN_POINT('',(-3.51273611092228,-7.00039031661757,12.4178393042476));
#1042=CARTESIAN_POINT('',(-3.45437012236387,-7.0870601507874,12.3660279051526));
#1043=CARTESIAN_POINT('',(-3.42893113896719,-7.13121748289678,12.3373337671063));
#1044=CARTESIAN_POINT('',(-3.39384524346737,-7.20208570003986,12.2883604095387));
#1045=CARTESIAN_POINT('',(-3.38197627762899,-7.22861528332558,12.2693831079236));
#1046=CARTESIAN_POINT('',(-3.37125565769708,-7.25513557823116,12.2498526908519));
#1047=B_SPLINE_CURVE_WITH_KNOTS('',3,(#1023,#1024,#1025,#1026,#1027,#1028,#1029,#1030,#1031,
#1032,#1033,#1034,#1035,#1036,#1037,#1038,#1039,#1040,#1041,#1042,#1043,#1044,#1045,#1046),
.UNSPECIFIED.,.F.,.F.,(4,2,2,2,2,2,2,2,2,2,2,4),(0.,0.175410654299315,0.352568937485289,
0.497765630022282,0.642428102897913,0.788331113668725,0.934270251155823,1.06287477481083,
1.19154289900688,1.36616525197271,1.54099757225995,1.64498268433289),.UNSPECIFIED.);
#1048=CARTESIAN_POINT('',(-3.37133649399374,-7.25493557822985,12.25));
#1049=VERTEX_POINT('',#1048);
#1050=EDGE_CURVE('E516',#1020,#1049,#1047,.T.);
#1051=ORIENTED_EDGE('',*,*,#1050,.T.);
#1052=EDGE_CURVE('E627',#260,#1049,#994,.T.);
#1053=ORIENTED_EDGE('',*,*,#1052,.F.);
#1054=ORIENTED_EDGE('',*,*,#297,.T.);
#1055=EDGE_CURVE('E629',#328,#269,#994,.T.);
#1056=ORIENTED_EDGE('',*,*,#1055,.F.);
#1057=ORIENTED_EDGE('',*,*,#365,.T.);
#1058=EDGE_CURVE('E632',#396,#337,#994,.T.);
#1059=ORIENTED_EDGE('',*,*,#1058,.F.);
#1060=ORIENTED_EDGE('',*,*,#433,.T.);
#1061=EDGE_LOOP('',(#996,#997,#999,#1000,#1002,#1003,#1005,#1006,#1008,#1009,#1011,#1012,#1014,
#1015,#1017,#1018,#1022,#1051,#1053,#1054,#1056,#1057,#1059,#1060));
#1062=FACE_BOUND('',#1061,.T.);
#1063=ADVANCED_FACE('F371',(#989,#1062),#986,.T.);
#1064=CARTESIAN_POINT('',(-4.43750000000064,-7.68597545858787,6.8));
#1065=DIRECTION('',(0.,0.,-1.));
#1066=DIRECTION('',(0.,-1.,0.));
#1067=AXIS2_PLACEMENT_3D('',#1064,#1065,#1066);
#1068=CIRCLE('',#1067,1.15);
#1069=CARTESIAN_POINT('',(-4.59729026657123,-6.54713083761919,6.8));
#1070=VERTEX_POINT('',#1069);
#1071=CARTESIAN_POINT('',(-3.37133649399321,-7.25493557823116,6.8));
#1072=VERTEX_POINT('',#1071);
#1073=EDGE_CURVE('E272',#1070,#1072,#1068,.T.);
#1074=ORIENTED_EDGE('',*,*,#1073,.F.);
#1075=EDGE_CURVE('E226',#1072,#1070,#244,.F.);
#1076=ORIENTED_EDGE('',*,*,#1075,.F.);
#1077=EDGE_LOOP('',(#1074,#1076));
#1078=FACE_BOUND('',#1077,.T.);
#1079=ADVANCED_FACE('F388',(#1078),#228,.T.);
#1080=CARTESIAN_POINT('',(-4.43750000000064,-7.68597545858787,6.8));
#1081=DIRECTION('',(0.,0.,1.));
#1082=DIRECTION('',(0.,-1.,0.));
#1083=AXIS2_PLACEMENT_3D('',#1080,#1081,#1082);
#1084=CYLINDRICAL_SURFACE('',#1083,1.15);
#1085=DIRECTION('',(0.,0.,1.));
#1086=VECTOR('',#1085,1.);
#1087=CARTESIAN_POINT('',(-4.59729026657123,-6.54713083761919,6.8));
#1088=LINE('',#1087,#1086);
#1089=EDGE_CURVE('E305',#1070,#1020,#1088,.T.);
#1090=ORIENTED_EDGE('',*,*,#1089,.F.);
#1091=ORIENTED_EDGE('',*,*,#1073,.T.);
#1092=DIRECTION('',(0.,0.,1.));
#1093=VECTOR('',#1092,1.);
#1094=CARTESIAN_POINT('',(-3.37133649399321,-7.25493557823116,6.8));
#1095=LINE('',#1094,#1093);
#1096=EDGE_CURVE('E303',#1072,#1049,#1095,.T.);
#1097=ORIENTED_EDGE('',*,*,#1096,.T.);
#1098=ORIENTED_EDGE('',*,*,#1050,.F.);
#1099=EDGE_LOOP('',(#1090,#1091,#1097,#1098));
#1100=FACE_BOUND('',#1099,.T.);
#1101=ADVANCED_FACE('F434',(#1100),#1084,.F.);
#1102=CARTESIAN_POINT('',(0.,0.,0.));
#1103=DIRECTION('',(0.,0.,-1.));
#1104=DIRECTION('',(0.,1.,0.));
#1105=AXIS2_PLACEMENT_3D('',#1102,#1103,#1104);
#1106=CYLINDRICAL_SURFACE('',#1105,8.);
#1107=CARTESIAN_POINT('',(0.,0.,5.75));
#1108=DIRECTION('',(0.,0.,-1.));
#1109=DIRECTION('',(-1.,0.,0.));
#1110=AXIS2_PLACEMENT_3D('',#1107,#1108,#1109);
#1111=CIRCLE('',#1110,8.);
#1112=CARTESIAN_POINT('',(-8.,0.,5.75));
#1113=VERTEX_POINT('',#1112);
#1114=EDGE_CURVE('E439',#1113,#1113,#1111,.F.);
#1115=ORIENTED_EDGE('',*,*,#1114,.T.);
#1116=EDGE_LOOP('',(#1115));
#1117=FACE_BOUND('',#1116,.T.);
#1118=ORIENTED_EDGE('',*,*,#1096,.F.);
#1119=ORIENTED_EDGE('',*,*,#1075,.T.);
#1120=ORIENTED_EDGE('',*,*,#1089,.T.);
#1121=ORIENTED_EDGE('',*,*,#1021,.T.);
#1122=ORIENTED_EDGE('',*,*,#950,.F.);
#1123=ORIENTED_EDGE('',*,*,#925,.T.);
#1124=ORIENTED_EDGE('',*,*,#941,.T.);
#1125=ORIENTED_EDGE('',*,*,#1016,.T.);
#1126=ORIENTED_EDGE('',*,*,#882,.F.);
#1127=ORIENTED_EDGE('',*,*,#857,.T.);
#1128=ORIENTED_EDGE('',*,*,#873,.T.);
#1129=ORIENTED_EDGE('',*,*,#1013,.T.);
#1130=ORIENTED_EDGE('',*,*,#814,.F.);
#1131=ORIENTED_EDGE('',*,*,#789,.T.);
#1132=ORIENTED_EDGE('',*,*,#805,.T.);
#1133=ORIENTED_EDGE('',*,*,#1010,.T.);
#1134=ORIENTED_EDGE('',*,*,#746,.F.);
#1135=ORIENTED_EDGE('',*,*,#721,.T.);
#1136=ORIENTED_EDGE('',*,*,#737,.T.);
#1137=ORIENTED_EDGE('',*,*,#1007,.T.);
#1138=ORIENTED_EDGE('',*,*,#678,.F.);
#1139=ORIENTED_EDGE('',*,*,#653,.T.);
#1140=ORIENTED_EDGE('',*,*,#669,.T.);
#1141=ORIENTED_EDGE('',*,*,#1004,.T.);
#1142=ORIENTED_EDGE('',*,*,#610,.F.);
#1143=ORIENTED_EDGE('',*,*,#585,.T.);
#1144=ORIENTED_EDGE('',*,*,#601,.T.);
#1145=ORIENTED_EDGE('',*,*,#1001,.T.);
#1146=ORIENTED_EDGE('',*,*,#542,.F.);
#1147=ORIENTED_EDGE('',*,*,#517,.T.);
#1148=ORIENTED_EDGE('',*,*,#533,.T.);
#1149=ORIENTED_EDGE('',*,*,#998,.T.);
#1150=ORIENTED_EDGE('',*,*,#474,.F.);
#1151=ORIENTED_EDGE('',*,*,#449,.T.);
#1152=ORIENTED_EDGE('',*,*,#465,.T.);
#1153=ORIENTED_EDGE('',*,*,#995,.T.);
#1154=ORIENTED_EDGE('',*,*,#406,.F.);
#1155=ORIENTED_EDGE('',*,*,#381,.T.);
#1156=ORIENTED_EDGE('',*,*,#397,.T.);
#1157=ORIENTED_EDGE('',*,*,#1058,.T.);
#1158=ORIENTED_EDGE('',*,*,#338,.F.);
#1159=ORIENTED_EDGE('',*,*,#313,.T.);
#1160=ORIENTED_EDGE('',*,*,#329,.T.);
#1161=ORIENTED_EDGE('',*,*,#1055,.T.);
#1162=ORIENTED_EDGE('',*,*,#270,.F.);
#1163=ORIENTED_EDGE('',*,*,#245,.T.);
#1164=ORIENTED_EDGE('',*,*,#261,.T.);
#1165=ORIENTED_EDGE('',*,*,#1052,.T.);
#1166=EDGE_LOOP('',(#1118,#1119,#1120,#1121,#1122,#1123,#1124,#1125,#1126,#1127,#1128,#1129,
#1130,#1131,#1132,#1133,#1134,#1135,#1136,#1137,#1138,#1139,#1140,#1141,#1142,#1143,#1144,#1145,
#1146,#1147,#1148,#1149,#1150,#1151,#1152,#1153,#1154,#1155,#1156,#1157,#1158,#1159,#1160,#1161,
#1162,#1163,#1164,#1165));
#1167=FACE_BOUND('',#1166,.T.);
#1168=ADVANCED_FACE('F198',(#1117,#1167),#1106,.T.);
#1169=CARTESIAN_POINT('',(0.,0.,5.));
#1170=DIRECTION('',(0.,0.,1.));
#1171=DIRECTION('',(1.,0.,0.));
#1172=AXIS2_PLACEMENT_3D('',#1169,#1170,#1171);
#1173=CONICAL_SURFACE('',#1172,7.25,0.785398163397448);
#1174=ORIENTED_EDGE('',*,*,#1114,.F.);
#1175=EDGE_LOOP('',(#1174));
#1176=FACE_BOUND('',#1175,.T.);
#1177=ORIENTED_EDGE('',*,*,#139,.F.);
#1178=EDGE_LOOP('',(#1177));
#1179=FACE_BOUND('',#1178,.T.);
#1180=ADVANCED_FACE('F422',(#1176,#1179),#1173,.T.);
#1181=CARTESIAN_POINT('',(0.,0.,6.));
#1182=DIRECTION('',(0.,0.,-1.));
#1183=DIRECTION('',(-1.,0.,0.));
#1184=AXIS2_PLACEMENT_3D('',#1181,#1182,#1183);
#1185=CYLINDRICAL_SURFACE('',#1184,2.);
#1186=CARTESIAN_POINT('',(0.,0.,0.4));
#1187=DIRECTION('',(0.,0.,-1.));
#1188=DIRECTION('',(-1.,0.,0.));
#1189=AXIS2_PLACEMENT_3D('',#1186,#1187,#1188);
#1190=CIRCLE('',#1189,2.);
#1191=CARTESIAN_POINT('',(-2.,0.,0.4));
#1192=VERTEX_POINT('',#1191);
#1193=EDGE_CURVE('E22',#1192,#1192,#1190,.T.);
#1194=ORIENTED_EDGE('',*,*,#1193,.T.);
#1195=EDGE_LOOP('',(#1194));
#1196=FACE_BOUND('',#1195,.T.);
#1197=CARTESIAN_POINT('',(0.,0.,6.));
#1198=DIRECTION('',(0.,0.,-1.));
#1199=DIRECTION('',(-1.,0.,0.));
#1200=AXIS2_PLACEMENT_3D('',#1197,#1198,#1199);
#1201=CIRCLE('',#1200,2.);
#1202=CARTESIAN_POINT('',(-2.,0.,6.));
#1203=VERTEX_POINT('',#1202);
#1204=EDGE_CURVE('E195',#1203,#1203,#1201,.T.);
#1205=ORIENTED_EDGE('',*,*,#1204,.F.);
#1206=EDGE_LOOP('',(#1205));
#1207=FACE_BOUND('',#1206,.T.);
#1208=ADVANCED_FACE('F424',(#1196,#1207),#1185,.F.);
#1209=CARTESIAN_POINT('',(0.,0.,6.));
#1210=DIRECTION('',(0.,0.,-1.));
#1211=DIRECTION('',(-1.,0.,0.));
#1212=AXIS2_PLACEMENT_3D('',#1209,#1210,#1211);
#1213=PLANE('',#1212);
#1214=ORIENTED_EDGE('',*,*,#1204,.T.);
#1215=EDGE_LOOP('',(#1214));
#1216=FACE_BOUND('',#1215,.T.);
#1217=ADVANCED_FACE('F431',(#1216),#1213,.T.);
#1218=CARTESIAN_POINT('',(0.,0.,0.4));
#1219=DIRECTION('',(0.,0.,-1.));
#1220=DIRECTION('',(-1.,0.,0.));
#1221=AXIS2_PLACEMENT_3D('',#1218,#1219,#1220);
#1222=CONICAL_SURFACE('',#1221,2.,0.785398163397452);
#1223=ORIENTED_EDGE('',*,*,#31,.F.);
#1224=EDGE_LOOP('',(#1223));
#1225=FACE_BOUND('',#1224,.T.);
#1226=ORIENTED_EDGE('',*,*,#1193,.F.);
#1227=EDGE_LOOP('',(#1226));
#1228=FACE_BOUND('',#1227,.T.);
#1229=ADVANCED_FACE('F16',(#1225,#1228),#1222,.F.);
#1230=CLOSED_SHELL('',(#46,#66,#86,#106,#126,#146,#163,#183,#203,#223,#249,#301,#317,#369,#385,
#437,#453,#505,#521,#573,#589,#641,#657,#709,#725,#777,#793,#845,#861,#913,#929,#981,#1063,
#1079,#1101,#1168,#1180,#1208,#1217,#1229));
#1231=MANIFOLD_SOLID_BREP('B1',#1230);
#1232=ADVANCED_BREP_SHAPE_REPRESENTATION('',(#18,#1231),#14);
#1233=SHAPE_DEFINITION_REPRESENTATION(#9,#1232);
ENDSEC;
END-ISO-10303-21;
